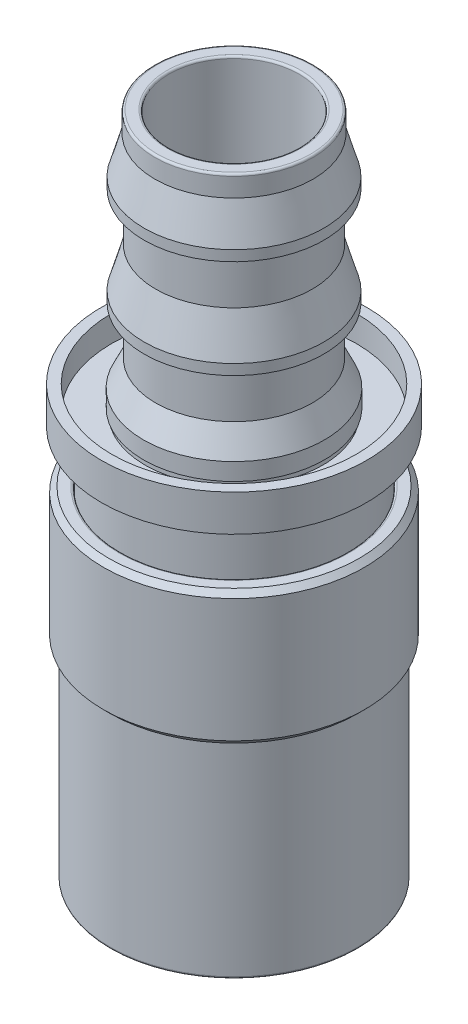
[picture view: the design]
ISO-10303-21;
HEADER;
FILE_DESCRIPTION(('STEP AP214'),'2;1');
FILE_NAME('part.step','',(''),(''),'','','');
FILE_SCHEMA(('AUTOMOTIVE_DESIGN { 1 0 10303 214 1 1 1 1 }'));
ENDSEC;
DATA;
#1=APPLICATION_CONTEXT('core data for automotive mechanical design processes');
#2=APPLICATION_PROTOCOL_DEFINITION('international standard','automotive_design',2000,#1);
#3=PRODUCT_CONTEXT('',#1,'mechanical');
#4=PRODUCT('Part','Part','',(#3));
#5=PRODUCT_RELATED_PRODUCT_CATEGORY('part','',(#4));
#6=PRODUCT_DEFINITION_FORMATION('','',#4);
#7=PRODUCT_DEFINITION_CONTEXT('part definition',#1,'design');
#8=PRODUCT_DEFINITION('design','',#6,#7);
#9=PRODUCT_DEFINITION_SHAPE('','',#8);
#10=(LENGTH_UNIT() NAMED_UNIT(*) SI_UNIT(.MILLI.,.METRE.));
#11=(NAMED_UNIT(*) PLANE_ANGLE_UNIT() SI_UNIT($,.RADIAN.));
#12=(NAMED_UNIT(*) SI_UNIT($,.STERADIAN.) SOLID_ANGLE_UNIT());
#13=UNCERTAINTY_MEASURE_WITH_UNIT(LENGTH_MEASURE(1.E-05),#10,'distance_accuracy_value','');
#14=(GEOMETRIC_REPRESENTATION_CONTEXT(3) GLOBAL_UNCERTAINTY_ASSIGNED_CONTEXT((#13)) GLOBAL_UNIT_ASSIGNED_CONTEXT((#10,
#11,#12)) REPRESENTATION_CONTEXT('',''));
#15=CARTESIAN_POINT('',(0.,0.,0.));
#16=DIRECTION('',(0.,0.,1.));
#17=DIRECTION('',(1.,0.,0.));
#18=AXIS2_PLACEMENT_3D('',#15,#16,#17);
#19=CARTESIAN_POINT('',(0.,80.6958,0.));
#20=DIRECTION('',(0.,1.,0.));
#21=DIRECTION('',(0.,0.,1.));
#22=AXIS2_PLACEMENT_3D('',#19,#20,#21);
#23=TOROIDAL_SURFACE('',#22,8.1788,0.254);
#24=CARTESIAN_POINT('',(0.,80.6958,0.));
#25=DIRECTION('',(0.,-1.,0.));
#26=DIRECTION('',(0.,0.,-1.));
#27=AXIS2_PLACEMENT_3D('',#24,#25,#26);
#28=CIRCLE('',#27,7.9248);
#29=CARTESIAN_POINT('',(0.,80.6958,7.9248));
#30=VERTEX_POINT('',#29);
#31=CARTESIAN_POINT('',(0.,80.6958,-7.9248));
#32=VERTEX_POINT('',#31);
#33=EDGE_CURVE('P0_E11',#30,#32,#28,.T.);
#34=ORIENTED_EDGE('',*,*,#33,.T.);
#35=CARTESIAN_POINT('',(0.,80.6958,-8.1788));
#36=DIRECTION('',(-1.,0.,0.));
#37=DIRECTION('',(0.,0.,-1.));
#38=AXIS2_PLACEMENT_3D('',#35,#36,#37);
#39=CIRCLE('',#38,0.254);
#40=CARTESIAN_POINT('',(0.,80.9498,-8.1788));
#41=VERTEX_POINT('',#40);
#42=EDGE_CURVE('P0_E27',#32,#41,#39,.T.);
#43=ORIENTED_EDGE('',*,*,#42,.T.);
#44=CARTESIAN_POINT('',(0.,80.9498,0.));
#45=DIRECTION('',(0.,1.,0.));
#46=DIRECTION('',(0.,0.,-1.));
#47=AXIS2_PLACEMENT_3D('',#44,#45,#46);
#48=CIRCLE('',#47,8.1788);
#49=CARTESIAN_POINT('',(0.,80.9498,8.1788));
#50=VERTEX_POINT('',#49);
#51=EDGE_CURVE('P0_E329',#41,#50,#48,.T.);
#52=ORIENTED_EDGE('',*,*,#51,.T.);
#53=CARTESIAN_POINT('',(0.,80.9498,0.));
#54=DIRECTION('',(0.,1.,0.));
#55=DIRECTION('',(0.,0.,-1.));
#56=AXIS2_PLACEMENT_3D('',#53,#54,#55);
#57=CIRCLE('',#56,8.1788);
#58=EDGE_CURVE('P0_E300',#50,#41,#57,.T.);
#59=ORIENTED_EDGE('',*,*,#58,.T.);
#60=ORIENTED_EDGE('',*,*,#42,.F.);
#61=CARTESIAN_POINT('',(0.,80.6958,0.));
#62=DIRECTION('',(0.,-1.,0.));
#63=DIRECTION('',(0.,0.,-1.));
#64=AXIS2_PLACEMENT_3D('',#61,#62,#63);
#65=CIRCLE('',#64,7.9248);
#66=EDGE_CURVE('P0_E41',#32,#30,#65,.T.);
#67=ORIENTED_EDGE('',*,*,#66,.T.);
#68=EDGE_LOOP('',(#34,#43,#52,#59,#60,#67));
#69=FACE_BOUND('',#68,.T.);
#70=ADVANCED_FACE('P0_F16',(#69),#23,.T.);
#71=CARTESIAN_POINT('',(0.,80.9498,7.9248));
#72=DIRECTION('',(0.,1.,0.));
#73=DIRECTION('',(1.,0.,0.));
#74=AXIS2_PLACEMENT_3D('',#71,#72,#73);
#75=PLANE('',#74);
#76=CARTESIAN_POINT('',(0.,80.9498,0.));
#77=DIRECTION('',(0.,-1.,0.));
#78=DIRECTION('',(0.,0.,-1.));
#79=AXIS2_PLACEMENT_3D('',#76,#77,#78);
#80=CIRCLE('',#79,9.37286457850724);
#81=CARTESIAN_POINT('',(0.,80.9498,9.37286457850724));
#82=VERTEX_POINT('',#81);
#83=CARTESIAN_POINT('',(0.,80.9498,-9.37286457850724));
#84=VERTEX_POINT('',#83);
#85=EDGE_CURVE('P0_E335',#82,#84,#80,.T.);
#86=ORIENTED_EDGE('',*,*,#85,.F.);
#87=CARTESIAN_POINT('',(0.,80.9498,0.));
#88=DIRECTION('',(0.,-1.,0.));
#89=DIRECTION('',(0.,0.,-1.));
#90=AXIS2_PLACEMENT_3D('',#87,#88,#89);
#91=CIRCLE('',#90,9.37286457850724);
#92=EDGE_CURVE('P0_E310',#84,#82,#91,.T.);
#93=ORIENTED_EDGE('',*,*,#92,.F.);
#94=EDGE_LOOP('',(#86,#93));
#95=FACE_BOUND('',#94,.T.);
#96=ORIENTED_EDGE('',*,*,#58,.F.);
#97=ORIENTED_EDGE('',*,*,#51,.F.);
#98=EDGE_LOOP('',(#96,#97));
#99=FACE_BOUND('',#98,.T.);
#100=ADVANCED_FACE('P0_F606',(#95,#99),#75,.T.);
#101=CARTESIAN_POINT('',(0.,52.4637,0.));
#102=DIRECTION('',(0.,1.,0.));
#103=DIRECTION('',(0.,0.,1.));
#104=AXIS2_PLACEMENT_3D('',#101,#102,#103);
#105=CYLINDRICAL_SURFACE('',#104,7.9248);
#106=ORIENTED_EDGE('',*,*,#33,.F.);
#107=ORIENTED_EDGE('',*,*,#66,.F.);
#108=DIRECTION('',(0.,-1.,0.));
#109=VECTOR('',#108,1.);
#110=CARTESIAN_POINT('',(0.,52.4637,-7.9248));
#111=LINE('',#110,#109);
#112=CARTESIAN_POINT('',(0.,23.9776,-7.9248));
#113=VERTEX_POINT('',#112);
#114=EDGE_CURVE('P0_E332',#32,#113,#111,.T.);
#115=ORIENTED_EDGE('',*,*,#114,.T.);
#116=CARTESIAN_POINT('',(0.,23.9776,0.));
#117=DIRECTION('',(0.,1.,0.));
#118=DIRECTION('',(1.,0.,0.));
#119=AXIS2_PLACEMENT_3D('',#116,#117,#118);
#120=CIRCLE('',#119,7.9248);
#121=CARTESIAN_POINT('',(0.,23.9776,7.9248));
#122=VERTEX_POINT('',#121);
#123=EDGE_CURVE('P0_E435',#122,#113,#120,.T.);
#124=ORIENTED_EDGE('',*,*,#123,.F.);
#125=CARTESIAN_POINT('',(0.,23.9776,0.));
#126=DIRECTION('',(0.,1.,0.));
#127=DIRECTION('',(1.,0.,0.));
#128=AXIS2_PLACEMENT_3D('',#125,#126,#127);
#129=CIRCLE('',#128,7.9248);
#130=EDGE_CURVE('P0_E506',#113,#122,#129,.T.);
#131=ORIENTED_EDGE('',*,*,#130,.F.);
#132=ORIENTED_EDGE('',*,*,#114,.F.);
#133=EDGE_LOOP('',(#106,#107,#115,#124,#131,#132));
#134=FACE_BOUND('',#133,.T.);
#135=ADVANCED_FACE('P0_F613',(#134),#105,.F.);
#136=CARTESIAN_POINT('',(0.,80.6958,0.));
#137=DIRECTION('',(0.,1.,0.));
#138=DIRECTION('',(0.,0.,1.));
#139=AXIS2_PLACEMENT_3D('',#136,#137,#138);
#140=TOROIDAL_SURFACE('',#139,9.37286457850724,0.254);
#141=ORIENTED_EDGE('',*,*,#85,.T.);
#142=CARTESIAN_POINT('',(0.,80.6958,-9.37286457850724));
#143=DIRECTION('',(-1.,0.,0.));
#144=DIRECTION('',(0.,0.,-1.));
#145=AXIS2_PLACEMENT_3D('',#142,#143,#144);
#146=CIRCLE('',#145,0.254);
#147=CARTESIAN_POINT('',(0.,80.6958,-9.62686457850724));
#148=VERTEX_POINT('',#147);
#149=EDGE_CURVE('P0_E415',#84,#148,#146,.T.);
#150=ORIENTED_EDGE('',*,*,#149,.T.);
#151=CARTESIAN_POINT('',(0.,80.6958,0.));
#152=DIRECTION('',(0.,1.,0.));
#153=DIRECTION('',(0.,0.,-1.));
#154=AXIS2_PLACEMENT_3D('',#151,#152,#153);
#155=CIRCLE('',#154,9.62686457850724);
#156=CARTESIAN_POINT('',(0.,80.6958,9.62686457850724));
#157=VERTEX_POINT('',#156);
#158=EDGE_CURVE('P0_E366',#148,#157,#155,.T.);
#159=ORIENTED_EDGE('',*,*,#158,.T.);
#160=CARTESIAN_POINT('',(0.,80.6958,0.));
#161=DIRECTION('',(0.,1.,0.));
#162=DIRECTION('',(0.,0.,-1.));
#163=AXIS2_PLACEMENT_3D('',#160,#161,#162);
#164=CIRCLE('',#163,9.62686457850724);
#165=EDGE_CURVE('P0_E363',#157,#148,#164,.T.);
#166=ORIENTED_EDGE('',*,*,#165,.T.);
#167=ORIENTED_EDGE('',*,*,#149,.F.);
#168=ORIENTED_EDGE('',*,*,#92,.T.);
#169=EDGE_LOOP('',(#141,#150,#159,#166,#167,#168));
#170=FACE_BOUND('',#169,.T.);
#171=ADVANCED_FACE('P0_F675',(#170),#140,.T.);
#172=CARTESIAN_POINT('',(0.,79.6798,0.));
#173=DIRECTION('',(0.,1.,0.));
#174=DIRECTION('',(0.,0.,1.));
#175=AXIS2_PLACEMENT_3D('',#172,#173,#174);
#176=CYLINDRICAL_SURFACE('',#175,9.62686457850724);
#177=ORIENTED_EDGE('',*,*,#165,.F.);
#178=ORIENTED_EDGE('',*,*,#158,.F.);
#179=DIRECTION('',(0.,-1.,0.));
#180=VECTOR('',#179,1.);
#181=CARTESIAN_POINT('',(0.,79.6798,-9.62686457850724));
#182=LINE('',#181,#180);
#183=CARTESIAN_POINT('',(0.,78.4098,-9.62686457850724));
#184=VERTEX_POINT('',#183);
#185=EDGE_CURVE('P0_E306',#148,#184,#182,.T.);
#186=ORIENTED_EDGE('',*,*,#185,.T.);
#187=CARTESIAN_POINT('',(0.,78.4098,0.));
#188=DIRECTION('',(0.,1.,0.));
#189=DIRECTION('',(1.,0.,0.));
#190=AXIS2_PLACEMENT_3D('',#187,#188,#189);
#191=CIRCLE('',#190,9.62686457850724);
#192=CARTESIAN_POINT('',(0.,78.4098,9.62686457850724));
#193=VERTEX_POINT('',#192);
#194=EDGE_CURVE('P0_E311',#184,#193,#191,.T.);
#195=ORIENTED_EDGE('',*,*,#194,.T.);
#196=CARTESIAN_POINT('',(0.,78.4098,0.));
#197=DIRECTION('',(0.,1.,0.));
#198=DIRECTION('',(1.,0.,0.));
#199=AXIS2_PLACEMENT_3D('',#196,#197,#198);
#200=CIRCLE('',#199,9.62686457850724);
#201=EDGE_CURVE('P0_E408',#193,#184,#200,.T.);
#202=ORIENTED_EDGE('',*,*,#201,.T.);
#203=ORIENTED_EDGE('',*,*,#185,.F.);
#204=EDGE_LOOP('',(#177,#178,#186,#195,#202,#203));
#205=FACE_BOUND('',#204,.T.);
#206=ADVANCED_FACE('P0_F686',(#205),#176,.T.);
#207=CARTESIAN_POINT('',(0.,0.254,0.));
#208=DIRECTION('',(0.,1.,0.));
#209=DIRECTION('',(0.,0.,1.));
#210=AXIS2_PLACEMENT_3D('',#207,#208,#209);
#211=TOROIDAL_SURFACE('',#210,11.8618,0.254);
#212=CARTESIAN_POINT('',(0.,0.254,0.));
#213=DIRECTION('',(0.,-1.,0.));
#214=DIRECTION('',(0.,0.,-1.));
#215=AXIS2_PLACEMENT_3D('',#212,#213,#214);
#216=CIRCLE('',#215,12.1158);
#217=CARTESIAN_POINT('',(0.,0.254,12.1158));
#218=VERTEX_POINT('',#217);
#219=CARTESIAN_POINT('',(0.,0.254,-12.1158));
#220=VERTEX_POINT('',#219);
#221=EDGE_CURVE('P0_E411',#218,#220,#216,.T.);
#222=ORIENTED_EDGE('',*,*,#221,.T.);
#223=CARTESIAN_POINT('',(0.,0.254,-11.8618));
#224=DIRECTION('',(-1.,0.,0.));
#225=DIRECTION('',(0.,0.,-1.));
#226=AXIS2_PLACEMENT_3D('',#223,#224,#225);
#227=CIRCLE('',#226,0.254);
#228=CARTESIAN_POINT('',(0.,0.,-11.8618));
#229=VERTEX_POINT('',#228);
#230=EDGE_CURVE('P0_E459',#220,#229,#227,.T.);
#231=ORIENTED_EDGE('',*,*,#230,.T.);
#232=CARTESIAN_POINT('',(0.,0.,0.));
#233=DIRECTION('',(0.,1.,0.));
#234=DIRECTION('',(0.,0.,-1.));
#235=AXIS2_PLACEMENT_3D('',#232,#233,#234);
#236=CIRCLE('',#235,11.8618);
#237=CARTESIAN_POINT('',(0.,0.,11.8618));
#238=VERTEX_POINT('',#237);
#239=EDGE_CURVE('P0_E443',#229,#238,#236,.T.);
#240=ORIENTED_EDGE('',*,*,#239,.T.);
#241=CARTESIAN_POINT('',(0.,0.,0.));
#242=DIRECTION('',(0.,1.,0.));
#243=DIRECTION('',(0.,0.,-1.));
#244=AXIS2_PLACEMENT_3D('',#241,#242,#243);
#245=CIRCLE('',#244,11.8618);
#246=EDGE_CURVE('P0_E440',#238,#229,#245,.T.);
#247=ORIENTED_EDGE('',*,*,#246,.T.);
#248=ORIENTED_EDGE('',*,*,#230,.F.);
#249=CARTESIAN_POINT('',(0.,0.254,0.));
#250=DIRECTION('',(0.,-1.,0.));
#251=DIRECTION('',(0.,0.,-1.));
#252=AXIS2_PLACEMENT_3D('',#249,#250,#251);
#253=CIRCLE('',#252,12.1158);
#254=EDGE_CURVE('P0_E399',#220,#218,#253,.T.);
#255=ORIENTED_EDGE('',*,*,#254,.T.);
#256=EDGE_LOOP('',(#222,#231,#240,#247,#248,#255));
#257=FACE_BOUND('',#256,.T.);
#258=ADVANCED_FACE('P0_F689',(#257),#211,.T.);
#259=CARTESIAN_POINT('',(0.,0.,12.1158));
#260=DIRECTION('',(0.,-1.,0.));
#261=DIRECTION('',(0.,0.,-1.));
#262=AXIS2_PLACEMENT_3D('',#259,#260,#261);
#263=PLANE('',#262);
#264=ORIENTED_EDGE('',*,*,#246,.F.);
#265=ORIENTED_EDGE('',*,*,#239,.F.);
#266=EDGE_LOOP('',(#264,#265));
#267=FACE_BOUND('',#266,.T.);
#268=CARTESIAN_POINT('',(0.,0.,0.));
#269=DIRECTION('',(0.,-1.,0.));
#270=DIRECTION('',(0.,0.,-1.));
#271=AXIS2_PLACEMENT_3D('',#268,#269,#270);
#272=CIRCLE('',#271,11.1760003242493);
#273=CARTESIAN_POINT('',(0.,0.,11.1760003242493));
#274=VERTEX_POINT('',#273);
#275=EDGE_CURVE('P0_E286',#274,#274,#272,.T.);
#276=ORIENTED_EDGE('',*,*,#275,.F.);
#277=EDGE_LOOP('',(#276));
#278=FACE_BOUND('',#277,.T.);
#279=ADVANCED_FACE('P0_F650',(#267,#278),#263,.T.);
#280=CARTESIAN_POINT('',(0.,8.1153,0.));
#281=DIRECTION('',(0.,1.,0.));
#282=DIRECTION('',(0.,0.,1.));
#283=AXIS2_PLACEMENT_3D('',#280,#281,#282);
#284=CYLINDRICAL_SURFACE('',#283,12.1158);
#285=CARTESIAN_POINT('',(0.,16.2306,0.));
#286=DIRECTION('',(0.,1.,0.));
#287=DIRECTION('',(1.,0.,0.));
#288=AXIS2_PLACEMENT_3D('',#285,#286,#287);
#289=CIRCLE('',#288,12.1158);
#290=CARTESIAN_POINT('',(0.,16.2306,12.1158));
#291=VERTEX_POINT('',#290);
#292=CARTESIAN_POINT('',(0.,16.2306,-12.1158));
#293=VERTEX_POINT('',#292);
#294=EDGE_CURVE('P0_E336',#291,#293,#289,.T.);
#295=ORIENTED_EDGE('',*,*,#294,.F.);
#296=CARTESIAN_POINT('',(0.,16.2306,0.));
#297=DIRECTION('',(0.,1.,0.));
#298=DIRECTION('',(1.,0.,0.));
#299=AXIS2_PLACEMENT_3D('',#296,#297,#298);
#300=CIRCLE('',#299,12.1158);
#301=EDGE_CURVE('P0_E280',#293,#291,#300,.T.);
#302=ORIENTED_EDGE('',*,*,#301,.F.);
#303=DIRECTION('',(0.,-1.,0.));
#304=VECTOR('',#303,1.);
#305=CARTESIAN_POINT('',(0.,8.1153,-12.1158));
#306=LINE('',#305,#304);
#307=EDGE_CURVE('P0_E395',#293,#220,#306,.T.);
#308=ORIENTED_EDGE('',*,*,#307,.T.);
#309=ORIENTED_EDGE('',*,*,#221,.F.);
#310=ORIENTED_EDGE('',*,*,#254,.F.);
#311=ORIENTED_EDGE('',*,*,#307,.F.);
#312=EDGE_LOOP('',(#295,#302,#308,#309,#310,#311));
#313=FACE_BOUND('',#312,.T.);
#314=ADVANCED_FACE('P0_F601',(#313),#284,.T.);
#315=CARTESIAN_POINT('',(0.,16.4846,0.));
#316=DIRECTION('',(0.,1.,0.));
#317=DIRECTION('',(0.,0.,1.));
#318=AXIS2_PLACEMENT_3D('',#315,#316,#317);
#319=TOROIDAL_SURFACE('',#318,13.4874,0.254);
#320=CARTESIAN_POINT('',(0.,16.4846,0.));
#321=DIRECTION('',(0.,-1.,0.));
#322=DIRECTION('',(0.,0.,-1.));
#323=AXIS2_PLACEMENT_3D('',#320,#321,#322);
#324=CIRCLE('',#323,13.7414);
#325=CARTESIAN_POINT('',(0.,16.4846,13.7414));
#326=VERTEX_POINT('',#325);
#327=CARTESIAN_POINT('',(0.,16.4846,-13.7414));
#328=VERTEX_POINT('',#327);
#329=EDGE_CURVE('P0_E400',#326,#328,#324,.T.);
#330=ORIENTED_EDGE('',*,*,#329,.T.);
#331=CARTESIAN_POINT('',(0.,16.4846,-13.4874));
#332=DIRECTION('',(-1.,0.,0.));
#333=DIRECTION('',(0.,0.,-1.));
#334=AXIS2_PLACEMENT_3D('',#331,#332,#333);
#335=CIRCLE('',#334,0.254);
#336=CARTESIAN_POINT('',(0.,16.2306,-13.4874));
#337=VERTEX_POINT('',#336);
#338=EDGE_CURVE('P0_E448',#328,#337,#335,.T.);
#339=ORIENTED_EDGE('',*,*,#338,.T.);
#340=CARTESIAN_POINT('',(0.,16.2306,0.));
#341=DIRECTION('',(0.,1.,0.));
#342=DIRECTION('',(0.,0.,-1.));
#343=AXIS2_PLACEMENT_3D('',#340,#341,#342);
#344=CIRCLE('',#343,13.4874);
#345=CARTESIAN_POINT('',(0.,16.2306,13.4874));
#346=VERTEX_POINT('',#345);
#347=EDGE_CURVE('P0_E488',#337,#346,#344,.T.);
#348=ORIENTED_EDGE('',*,*,#347,.T.);
#349=CARTESIAN_POINT('',(0.,16.2306,0.));
#350=DIRECTION('',(0.,1.,0.));
#351=DIRECTION('',(0.,0.,-1.));
#352=AXIS2_PLACEMENT_3D('',#349,#350,#351);
#353=CIRCLE('',#352,13.4874);
#354=EDGE_CURVE('P0_E451',#346,#337,#353,.T.);
#355=ORIENTED_EDGE('',*,*,#354,.T.);
#356=ORIENTED_EDGE('',*,*,#338,.F.);
#357=CARTESIAN_POINT('',(0.,16.4846,0.));
#358=DIRECTION('',(0.,-1.,0.));
#359=DIRECTION('',(0.,0.,-1.));
#360=AXIS2_PLACEMENT_3D('',#357,#358,#359);
#361=CIRCLE('',#360,13.7414);
#362=EDGE_CURVE('P0_E382',#328,#326,#361,.T.);
#363=ORIENTED_EDGE('',*,*,#362,.T.);
#364=EDGE_LOOP('',(#330,#339,#348,#355,#356,#363));
#365=FACE_BOUND('',#364,.T.);
#366=ADVANCED_FACE('P0_F584',(#365),#319,.T.);
#367=CARTESIAN_POINT('',(0.,31.9149084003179,0.));
#368=DIRECTION('',(0.,1.,0.));
#369=DIRECTION('',(0.,0.,1.));
#370=AXIS2_PLACEMENT_3D('',#367,#368,#369);
#371=CYLINDRICAL_SURFACE('',#370,13.7414);
#372=CARTESIAN_POINT('',(0.,47.3452168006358,0.));
#373=DIRECTION('',(0.,1.,0.));
#374=DIRECTION('',(0.,0.,-1.));
#375=AXIS2_PLACEMENT_3D('',#372,#373,#374);
#376=CIRCLE('',#375,13.7414);
#377=CARTESIAN_POINT('',(0.,47.3452168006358,13.7414));
#378=VERTEX_POINT('',#377);
#379=CARTESIAN_POINT('',(0.,47.3452168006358,-13.7414));
#380=VERTEX_POINT('',#379);
#381=EDGE_CURVE('P0_E285',#378,#380,#376,.T.);
#382=ORIENTED_EDGE('',*,*,#381,.F.);
#383=CARTESIAN_POINT('',(0.,47.3452168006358,0.));
#384=DIRECTION('',(0.,1.,0.));
#385=DIRECTION('',(0.,0.,-1.));
#386=AXIS2_PLACEMENT_3D('',#383,#384,#385);
#387=CIRCLE('',#386,13.7414);
#388=EDGE_CURVE('P0_E293',#380,#378,#387,.T.);
#389=ORIENTED_EDGE('',*,*,#388,.F.);
#390=DIRECTION('',(0.,-1.,0.));
#391=VECTOR('',#390,1.);
#392=CARTESIAN_POINT('',(0.,31.9149084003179,-13.7414));
#393=LINE('',#392,#391);
#394=EDGE_CURVE('P0_E340',#380,#328,#393,.T.);
#395=ORIENTED_EDGE('',*,*,#394,.T.);
#396=ORIENTED_EDGE('',*,*,#329,.F.);
#397=ORIENTED_EDGE('',*,*,#362,.F.);
#398=ORIENTED_EDGE('',*,*,#394,.F.);
#399=EDGE_LOOP('',(#382,#389,#395,#396,#397,#398));
#400=FACE_BOUND('',#399,.T.);
#401=ADVANCED_FACE('P0_F591',(#400),#371,.T.);
#402=CARTESIAN_POINT('',(0.,16.2306,13.7414));
#403=DIRECTION('',(0.,-1.,0.));
#404=DIRECTION('',(0.,0.,-1.));
#405=AXIS2_PLACEMENT_3D('',#402,#403,#404);
#406=PLANE('',#405);
#407=ORIENTED_EDGE('',*,*,#354,.F.);
#408=ORIENTED_EDGE('',*,*,#347,.F.);
#409=EDGE_LOOP('',(#407,#408));
#410=FACE_BOUND('',#409,.T.);
#411=ORIENTED_EDGE('',*,*,#294,.T.);
#412=ORIENTED_EDGE('',*,*,#301,.T.);
#413=EDGE_LOOP('',(#411,#412));
#414=FACE_BOUND('',#413,.T.);
#415=ADVANCED_FACE('P0_F586',(#410,#414),#406,.T.);
#416=CARTESIAN_POINT('',(0.,47.3452168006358,0.));
#417=DIRECTION('',(0.,1.,0.));
#418=DIRECTION('',(0.,0.,1.));
#419=AXIS2_PLACEMENT_3D('',#416,#417,#418);
#420=TOROIDAL_SURFACE('',#419,13.4874,0.254);
#421=CARTESIAN_POINT('',(0.,47.5992168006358,0.));
#422=DIRECTION('',(0.,-1.,0.));
#423=DIRECTION('',(0.,0.,-1.));
#424=AXIS2_PLACEMENT_3D('',#421,#422,#423);
#425=CIRCLE('',#424,13.4874);
#426=CARTESIAN_POINT('',(0.,47.5992168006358,13.4874));
#427=VERTEX_POINT('',#426);
#428=CARTESIAN_POINT('',(0.,47.5992168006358,-13.4874));
#429=VERTEX_POINT('',#428);
#430=EDGE_CURVE('P0_E272',#427,#429,#425,.T.);
#431=ORIENTED_EDGE('',*,*,#430,.T.);
#432=CARTESIAN_POINT('',(0.,47.3452168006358,-13.4874));
#433=DIRECTION('',(-1.,0.,0.));
#434=DIRECTION('',(0.,0.,-1.));
#435=AXIS2_PLACEMENT_3D('',#432,#433,#434);
#436=CIRCLE('',#435,0.254);
#437=EDGE_CURVE('P0_E281',#429,#380,#436,.T.);
#438=ORIENTED_EDGE('',*,*,#437,.T.);
#439=ORIENTED_EDGE('',*,*,#388,.T.);
#440=ORIENTED_EDGE('',*,*,#381,.T.);
#441=ORIENTED_EDGE('',*,*,#437,.F.);
#442=CARTESIAN_POINT('',(0.,47.5992168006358,0.));
#443=DIRECTION('',(0.,-1.,0.));
#444=DIRECTION('',(0.,0.,-1.));
#445=AXIS2_PLACEMENT_3D('',#442,#443,#444);
#446=CIRCLE('',#445,13.4874);
#447=EDGE_CURVE('P0_E276',#429,#427,#446,.T.);
#448=ORIENTED_EDGE('',*,*,#447,.T.);
#449=EDGE_LOOP('',(#431,#438,#439,#440,#441,#448));
#450=FACE_BOUND('',#449,.T.);
#451=ADVANCED_FACE('P0_F283',(#450),#420,.T.);
#452=CARTESIAN_POINT('',(0.,47.5992168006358,10.4648));
#453=DIRECTION('',(0.,1.,0.));
#454=DIRECTION('',(1.,0.,0.));
#455=AXIS2_PLACEMENT_3D('',#452,#453,#454);
#456=PLANE('',#455);
#457=ORIENTED_EDGE('',*,*,#430,.F.);
#458=ORIENTED_EDGE('',*,*,#447,.F.);
#459=EDGE_LOOP('',(#457,#458));
#460=FACE_BOUND('',#459,.T.);
#461=CARTESIAN_POINT('',(0.,47.5992168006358,0.));
#462=DIRECTION('',(0.,1.,0.));
#463=DIRECTION('',(1.,0.,0.));
#464=AXIS2_PLACEMENT_3D('',#461,#462,#463);
#465=CIRCLE('',#464,10.4648);
#466=CARTESIAN_POINT('',(0.,47.5992168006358,10.4648));
#467=VERTEX_POINT('',#466);
#468=CARTESIAN_POINT('',(0.,47.5992168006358,-10.4648));
#469=VERTEX_POINT('',#468);
#470=EDGE_CURVE('P0_E318',#467,#469,#465,.T.);
#471=ORIENTED_EDGE('',*,*,#470,.F.);
#472=CARTESIAN_POINT('',(0.,47.5992168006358,0.));
#473=DIRECTION('',(0.,1.,0.));
#474=DIRECTION('',(1.,0.,0.));
#475=AXIS2_PLACEMENT_3D('',#472,#473,#474);
#476=CIRCLE('',#475,10.4648);
#477=EDGE_CURVE('P0_E321',#469,#467,#476,.T.);
#478=ORIENTED_EDGE('',*,*,#477,.F.);
#479=EDGE_LOOP('',(#471,#478));
#480=FACE_BOUND('',#479,.T.);
#481=ADVANCED_FACE('P0_F274',(#460,#480),#456,.T.);
#482=CARTESIAN_POINT('',(0.,0.508,0.));
#483=DIRECTION('',(0.,-1.,0.));
#484=DIRECTION('',(0.,0.,-1.));
#485=AXIS2_PLACEMENT_3D('',#482,#483,#484);
#486=CONICAL_SURFACE('',#485,10.6680003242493,0.785398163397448);
#487=ORIENTED_EDGE('',*,*,#275,.T.);
#488=DIRECTION('',(0.,0.707106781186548,-0.707106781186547));
#489=VECTOR('',#488,1.);
#490=CARTESIAN_POINT('',(0.,0.508,10.6680003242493));
#491=LINE('',#490,#489);
#492=CARTESIAN_POINT('',(0.,1.016,10.1600003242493));
#493=VERTEX_POINT('',#492);
#494=EDGE_CURVE('P0_E296',#274,#493,#491,.T.);
#495=ORIENTED_EDGE('',*,*,#494,.T.);
#496=CARTESIAN_POINT('',(0.,1.016,0.));
#497=DIRECTION('',(0.,1.,0.));
#498=DIRECTION('',(0.,0.,-1.));
#499=AXIS2_PLACEMENT_3D('',#496,#497,#498);
#500=CIRCLE('',#499,10.1600003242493);
#501=CARTESIAN_POINT('',(0.,1.016,-10.1600003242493));
#502=VERTEX_POINT('',#501);
#503=EDGE_CURVE('P0_E418',#493,#502,#500,.T.);
#504=ORIENTED_EDGE('',*,*,#503,.T.);
#505=CARTESIAN_POINT('',(0.,1.016,0.));
#506=DIRECTION('',(0.,1.,0.));
#507=DIRECTION('',(0.,0.,-1.));
#508=AXIS2_PLACEMENT_3D('',#505,#506,#507);
#509=CIRCLE('',#508,10.1600003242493);
#510=EDGE_CURVE('P0_E422',#502,#493,#509,.T.);
#511=ORIENTED_EDGE('',*,*,#510,.T.);
#512=ORIENTED_EDGE('',*,*,#494,.F.);
#513=EDGE_LOOP('',(#487,#495,#504,#511,#512));
#514=FACE_BOUND('',#513,.T.);
#515=ADVANCED_FACE('P0_F629',(#514),#486,.F.);
#516=CARTESIAN_POINT('',(0.,8.59790016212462,0.));
#517=DIRECTION('',(0.,1.,0.));
#518=DIRECTION('',(0.,0.,1.));
#519=AXIS2_PLACEMENT_3D('',#516,#517,#518);
#520=CYLINDRICAL_SURFACE('',#519,10.1600003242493);
#521=CARTESIAN_POINT('',(0.,17.1958003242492,0.));
#522=DIRECTION('',(0.,1.,0.));
#523=DIRECTION('',(1.,0.,0.));
#524=AXIS2_PLACEMENT_3D('',#521,#522,#523);
#525=CIRCLE('',#524,10.1600003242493);
#526=CARTESIAN_POINT('',(0.,17.1958003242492,10.1600003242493));
#527=VERTEX_POINT('',#526);
#528=CARTESIAN_POINT('',(0.,17.1958003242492,-10.1600003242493));
#529=VERTEX_POINT('',#528);
#530=EDGE_CURVE('P0_E355',#527,#529,#525,.T.);
#531=ORIENTED_EDGE('',*,*,#530,.T.);
#532=DIRECTION('',(0.,-1.,0.));
#533=VECTOR('',#532,1.);
#534=CARTESIAN_POINT('',(0.,8.59790016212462,-10.1600003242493));
#535=LINE('',#534,#533);
#536=EDGE_CURVE('P0_E351',#529,#502,#535,.T.);
#537=ORIENTED_EDGE('',*,*,#536,.T.);
#538=ORIENTED_EDGE('',*,*,#503,.F.);
#539=ORIENTED_EDGE('',*,*,#510,.F.);
#540=ORIENTED_EDGE('',*,*,#536,.F.);
#541=CARTESIAN_POINT('',(0.,17.1958003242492,0.));
#542=DIRECTION('',(0.,1.,0.));
#543=DIRECTION('',(1.,0.,0.));
#544=AXIS2_PLACEMENT_3D('',#541,#542,#543);
#545=CIRCLE('',#544,10.1600003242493);
#546=EDGE_CURVE('P0_E356',#529,#527,#545,.T.);
#547=ORIENTED_EDGE('',*,*,#546,.T.);
#548=EDGE_LOOP('',(#531,#537,#538,#539,#540,#547));
#549=FACE_BOUND('',#548,.T.);
#550=ADVANCED_FACE('P0_F638',(#549),#520,.F.);
#551=CARTESIAN_POINT('',(0.,23.9776,10.668));
#552=DIRECTION('',(0.,-1.,0.));
#553=DIRECTION('',(0.,0.,-1.));
#554=AXIS2_PLACEMENT_3D('',#551,#552,#553);
#555=PLANE('',#554);
#556=CARTESIAN_POINT('',(0.,23.9776,0.));
#557=DIRECTION('',(0.,1.,0.));
#558=DIRECTION('',(1.,0.,0.));
#559=AXIS2_PLACEMENT_3D('',#556,#557,#558);
#560=CIRCLE('',#559,10.668);
#561=CARTESIAN_POINT('',(0.,23.9776,10.668));
#562=VERTEX_POINT('',#561);
#563=CARTESIAN_POINT('',(0.,23.9776,-10.668));
#564=VERTEX_POINT('',#563);
#565=EDGE_CURVE('P0_E501',#562,#564,#560,.T.);
#566=ORIENTED_EDGE('',*,*,#565,.F.);
#567=CARTESIAN_POINT('',(0.,23.9776,0.));
#568=DIRECTION('',(0.,1.,0.));
#569=DIRECTION('',(1.,0.,0.));
#570=AXIS2_PLACEMENT_3D('',#567,#568,#569);
#571=CIRCLE('',#570,10.668);
#572=EDGE_CURVE('P0_E20',#564,#562,#571,.T.);
#573=ORIENTED_EDGE('',*,*,#572,.F.);
#574=EDGE_LOOP('',(#566,#573));
#575=FACE_BOUND('',#574,.T.);
#576=ORIENTED_EDGE('',*,*,#123,.T.);
#577=ORIENTED_EDGE('',*,*,#130,.T.);
#578=EDGE_LOOP('',(#576,#577));
#579=FACE_BOUND('',#578,.T.);
#580=ADVANCED_FACE('P0_F635',(#575,#579),#555,.T.);
#581=CARTESIAN_POINT('',(0.,20.8407,0.));
#582=DIRECTION('',(0.,1.,0.));
#583=DIRECTION('',(0.,0.,1.));
#584=AXIS2_PLACEMENT_3D('',#581,#582,#583);
#585=CYLINDRICAL_SURFACE('',#584,10.668);
#586=ORIENTED_EDGE('',*,*,#565,.T.);
#587=DIRECTION('',(0.,-1.,0.));
#588=VECTOR('',#587,1.);
#589=CARTESIAN_POINT('',(0.,20.8407,-10.668));
#590=LINE('',#589,#588);
#591=CARTESIAN_POINT('',(0.,17.7038,-10.668));
#592=VERTEX_POINT('',#591);
#593=EDGE_CURVE('P0_E497',#564,#592,#590,.T.);
#594=ORIENTED_EDGE('',*,*,#593,.T.);
#595=CARTESIAN_POINT('',(0.,17.7038,0.));
#596=DIRECTION('',(0.,1.,0.));
#597=DIRECTION('',(1.,0.,0.));
#598=AXIS2_PLACEMENT_3D('',#595,#596,#597);
#599=CIRCLE('',#598,10.668);
#600=CARTESIAN_POINT('',(0.,17.7038,10.668));
#601=VERTEX_POINT('',#600);
#602=EDGE_CURVE('P0_E361',#601,#592,#599,.T.);
#603=ORIENTED_EDGE('',*,*,#602,.F.);
#604=CARTESIAN_POINT('',(0.,17.7038,0.));
#605=DIRECTION('',(0.,1.,0.));
#606=DIRECTION('',(1.,0.,0.));
#607=AXIS2_PLACEMENT_3D('',#604,#605,#606);
#608=CIRCLE('',#607,10.668);
#609=EDGE_CURVE('P0_E362',#592,#601,#608,.T.);
#610=ORIENTED_EDGE('',*,*,#609,.F.);
#611=ORIENTED_EDGE('',*,*,#593,.F.);
#612=ORIENTED_EDGE('',*,*,#572,.T.);
#613=EDGE_LOOP('',(#586,#594,#603,#610,#611,#612));
#614=FACE_BOUND('',#613,.T.);
#615=ADVANCED_FACE('P0_F623',(#614),#585,.F.);
#616=CARTESIAN_POINT('',(0.,17.4498001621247,0.));
#617=DIRECTION('',(0.,1.,0.));
#618=DIRECTION('',(0.,0.,1.));
#619=AXIS2_PLACEMENT_3D('',#616,#617,#618);
#620=CONICAL_SURFACE('',#619,10.4140001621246,0.785398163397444);
#621=ORIENTED_EDGE('',*,*,#602,.T.);
#622=DIRECTION('',(0.,-0.707106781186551,0.707106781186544));
#623=VECTOR('',#622,1.);
#624=CARTESIAN_POINT('',(0.,17.4498001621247,-10.4140001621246));
#625=LINE('',#624,#623);
#626=EDGE_CURVE('P0_E357',#592,#529,#625,.T.);
#627=ORIENTED_EDGE('',*,*,#626,.T.);
#628=ORIENTED_EDGE('',*,*,#530,.F.);
#629=ORIENTED_EDGE('',*,*,#546,.F.);
#630=ORIENTED_EDGE('',*,*,#626,.F.);
#631=ORIENTED_EDGE('',*,*,#609,.T.);
#632=EDGE_LOOP('',(#621,#627,#628,#629,#630,#631));
#633=FACE_BOUND('',#632,.T.);
#634=ADVANCED_FACE('P0_F619',(#633),#620,.F.);
#635=CARTESIAN_POINT('',(0.,48.5646084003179,0.));
#636=DIRECTION('',(0.,1.,0.));
#637=DIRECTION('',(0.,0.,1.));
#638=AXIS2_PLACEMENT_3D('',#635,#636,#637);
#639=CYLINDRICAL_SURFACE('',#638,10.4648);
#640=CARTESIAN_POINT('',(0.,49.53,0.));
#641=DIRECTION('',(0.,1.,0.));
#642=DIRECTION('',(1.,0.,0.));
#643=AXIS2_PLACEMENT_3D('',#640,#641,#642);
#644=CIRCLE('',#643,10.4648);
#645=CARTESIAN_POINT('',(0.,49.53,10.4648));
#646=VERTEX_POINT('',#645);
#647=CARTESIAN_POINT('',(0.,49.53,-10.4648));
#648=VERTEX_POINT('',#647);
#649=EDGE_CURVE('P0_E322',#646,#648,#644,.T.);
#650=ORIENTED_EDGE('',*,*,#649,.F.);
#651=CARTESIAN_POINT('',(0.,49.53,0.));
#652=DIRECTION('',(0.,1.,0.));
#653=DIRECTION('',(1.,0.,0.));
#654=AXIS2_PLACEMENT_3D('',#651,#652,#653);
#655=CIRCLE('',#654,10.4648);
#656=EDGE_CURVE('P0_E378',#648,#646,#655,.T.);
#657=ORIENTED_EDGE('',*,*,#656,.F.);
#658=DIRECTION('',(0.,-1.,0.));
#659=VECTOR('',#658,1.);
#660=CARTESIAN_POINT('',(0.,48.5646084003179,-10.4648));
#661=LINE('',#660,#659);
#662=EDGE_CURVE('P0_E350',#648,#469,#661,.T.);
#663=ORIENTED_EDGE('',*,*,#662,.T.);
#664=ORIENTED_EDGE('',*,*,#477,.T.);
#665=ORIENTED_EDGE('',*,*,#470,.T.);
#666=ORIENTED_EDGE('',*,*,#662,.F.);
#667=EDGE_LOOP('',(#650,#657,#663,#664,#665,#666));
#668=FACE_BOUND('',#667,.T.);
#669=ADVANCED_FACE('P0_F622',(#668),#639,.T.);
#670=CARTESIAN_POINT('',(0.,49.53,10.9982));
#671=DIRECTION('',(0.,-1.,0.));
#672=DIRECTION('',(0.,0.,-1.));
#673=AXIS2_PLACEMENT_3D('',#670,#671,#672);
#674=PLANE('',#673);
#675=CARTESIAN_POINT('',(0.,49.53,0.));
#676=DIRECTION('',(0.,1.,0.));
#677=DIRECTION('',(1.,0.,0.));
#678=AXIS2_PLACEMENT_3D('',#675,#676,#677);
#679=CIRCLE('',#678,10.9982);
#680=CARTESIAN_POINT('',(0.,49.53,10.9982));
#681=VERTEX_POINT('',#680);
#682=CARTESIAN_POINT('',(0.,49.53,-10.9982));
#683=VERTEX_POINT('',#682);
#684=EDGE_CURVE('P0_E394',#681,#683,#679,.T.);
#685=ORIENTED_EDGE('',*,*,#684,.F.);
#686=CARTESIAN_POINT('',(0.,49.53,0.));
#687=DIRECTION('',(0.,1.,0.));
#688=DIRECTION('',(1.,0.,0.));
#689=AXIS2_PLACEMENT_3D('',#686,#687,#688);
#690=CIRCLE('',#689,10.9982);
#691=EDGE_CURVE('P0_E389',#683,#681,#690,.T.);
#692=ORIENTED_EDGE('',*,*,#691,.F.);
#693=EDGE_LOOP('',(#685,#692));
#694=FACE_BOUND('',#693,.T.);
#695=ORIENTED_EDGE('',*,*,#649,.T.);
#696=ORIENTED_EDGE('',*,*,#656,.T.);
#697=EDGE_LOOP('',(#695,#696));
#698=FACE_BOUND('',#697,.T.);
#699=ADVANCED_FACE('P0_F661',(#694,#698),#674,.T.);
#700=CARTESIAN_POINT('',(0.,50.5792613,0.));
#701=DIRECTION('',(0.,-1.,0.));
#702=DIRECTION('',(0.,0.,1.));
#703=AXIS2_PLACEMENT_3D('',#700,#701,#702);
#704=CONICAL_SURFACE('',#703,10.9981976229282,2.26546661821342E-06);
#705=CARTESIAN_POINT('',(0.,51.6285226,0.));
#706=DIRECTION('',(0.,1.,0.));
#707=DIRECTION('',(1.,0.,0.));
#708=AXIS2_PLACEMENT_3D('',#705,#706,#707);
#709=CIRCLE('',#708,10.9981952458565);
#710=CARTESIAN_POINT('',(0.,51.6285226,10.9981952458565));
#711=VERTEX_POINT('',#710);
#712=CARTESIAN_POINT('',(0.,51.6285226,-10.9981952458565));
#713=VERTEX_POINT('',#712);
#714=EDGE_CURVE('P0_E407',#711,#713,#709,.T.);
#715=ORIENTED_EDGE('',*,*,#714,.F.);
#716=CARTESIAN_POINT('',(0.,51.6285226,0.));
#717=DIRECTION('',(0.,1.,0.));
#718=DIRECTION('',(1.,0.,0.));
#719=AXIS2_PLACEMENT_3D('',#716,#717,#718);
#720=CIRCLE('',#719,10.9981952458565);
#721=EDGE_CURVE('P0_E472',#713,#711,#720,.T.);
#722=ORIENTED_EDGE('',*,*,#721,.F.);
#723=DIRECTION('',(0.,-0.999999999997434,-2.26547168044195E-06));
#724=VECTOR('',#723,1.);
#725=CARTESIAN_POINT('',(0.,50.5792613,-10.9981976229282));
#726=LINE('',#725,#724);
#727=EDGE_CURVE('P0_E393',#713,#683,#726,.T.);
#728=ORIENTED_EDGE('',*,*,#727,.T.);
#729=ORIENTED_EDGE('',*,*,#691,.T.);
#730=ORIENTED_EDGE('',*,*,#684,.T.);
#731=ORIENTED_EDGE('',*,*,#727,.F.);
#732=EDGE_LOOP('',(#715,#722,#728,#729,#730,#731));
#733=FACE_BOUND('',#732,.T.);
#734=ADVANCED_FACE('P0_F634',(#733),#704,.T.);
#735=CARTESIAN_POINT('',(0.,53.2081613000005,0.));
#736=DIRECTION('',(0.,-1.,0.));
#737=DIRECTION('',(0.,0.,1.));
#738=AXIS2_PLACEMENT_3D('',#735,#736,#737);
#739=CONICAL_SURFACE('',#738,10.2615976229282,0.436332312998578);
#740=CARTESIAN_POINT('',(0.,54.787800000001,0.));
#741=DIRECTION('',(0.,1.,0.));
#742=DIRECTION('',(1.,0.,0.));
#743=AXIS2_PLACEMENT_3D('',#740,#741,#742);
#744=CIRCLE('',#743,9.525);
#745=CARTESIAN_POINT('',(0.,54.787800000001,9.525));
#746=VERTEX_POINT('',#745);
#747=CARTESIAN_POINT('',(0.,54.787800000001,-9.525));
#748=VERTEX_POINT('',#747);
#749=EDGE_CURVE('P0_E328',#746,#748,#744,.T.);
#750=ORIENTED_EDGE('',*,*,#749,.F.);
#751=CARTESIAN_POINT('',(0.,54.787800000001,0.));
#752=DIRECTION('',(0.,1.,0.));
#753=DIRECTION('',(1.,0.,0.));
#754=AXIS2_PLACEMENT_3D('',#751,#752,#753);
#755=CIRCLE('',#754,9.525);
#756=EDGE_CURVE('P0_E323',#748,#746,#755,.T.);
#757=ORIENTED_EDGE('',*,*,#756,.F.);
#758=DIRECTION('',(0.,-0.906307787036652,-0.422618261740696));
#759=VECTOR('',#758,1.);
#760=CARTESIAN_POINT('',(0.,53.2081613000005,-10.2615976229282));
#761=LINE('',#760,#759);
#762=EDGE_CURVE('P0_E535',#748,#713,#761,.T.);
#763=ORIENTED_EDGE('',*,*,#762,.T.);
#764=ORIENTED_EDGE('',*,*,#721,.T.);
#765=ORIENTED_EDGE('',*,*,#714,.T.);
#766=ORIENTED_EDGE('',*,*,#762,.F.);
#767=EDGE_LOOP('',(#750,#757,#763,#764,#765,#766));
#768=FACE_BOUND('',#767,.T.);
#769=ADVANCED_FACE('P0_F630',(#768),#739,.T.);
#770=CARTESIAN_POINT('',(0.,57.708800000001,0.));
#771=DIRECTION('',(0.,1.,0.));
#772=DIRECTION('',(0.,0.,1.));
#773=AXIS2_PLACEMENT_3D('',#770,#771,#772);
#774=CYLINDRICAL_SURFACE('',#773,9.525);
#775=CARTESIAN_POINT('',(0.,60.629800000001,0.));
#776=DIRECTION('',(0.,1.,0.));
#777=DIRECTION('',(1.,0.,0.));
#778=AXIS2_PLACEMENT_3D('',#775,#776,#777);
#779=CIRCLE('',#778,9.525);
#780=CARTESIAN_POINT('',(0.,60.629800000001,9.525));
#781=VERTEX_POINT('',#780);
#782=CARTESIAN_POINT('',(0.,60.629800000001,-9.525));
#783=VERTEX_POINT('',#782);
#784=EDGE_CURVE('P0_E431',#781,#783,#779,.T.);
#785=ORIENTED_EDGE('',*,*,#784,.F.);
#786=CARTESIAN_POINT('',(0.,60.629800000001,0.));
#787=DIRECTION('',(0.,1.,0.));
#788=DIRECTION('',(1.,0.,0.));
#789=AXIS2_PLACEMENT_3D('',#786,#787,#788);
#790=CIRCLE('',#789,9.525);
#791=EDGE_CURVE('P0_E479',#783,#781,#790,.T.);
#792=ORIENTED_EDGE('',*,*,#791,.F.);
#793=DIRECTION('',(0.,-1.,0.));
#794=VECTOR('',#793,1.);
#795=CARTESIAN_POINT('',(0.,57.708800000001,-9.525));
#796=LINE('',#795,#794);
#797=EDGE_CURVE('P0_E327',#783,#748,#796,.T.);
#798=ORIENTED_EDGE('',*,*,#797,.T.);
#799=ORIENTED_EDGE('',*,*,#756,.T.);
#800=ORIENTED_EDGE('',*,*,#749,.T.);
#801=ORIENTED_EDGE('',*,*,#797,.F.);
#802=EDGE_LOOP('',(#785,#792,#798,#799,#800,#801));
#803=FACE_BOUND('',#802,.T.);
#804=ADVANCED_FACE('P0_F633',(#803),#774,.T.);
#805=CARTESIAN_POINT('',(0.,60.6298,10.922));
#806=DIRECTION('',(0.,-1.,0.));
#807=DIRECTION('',(0.,0.,-1.));
#808=AXIS2_PLACEMENT_3D('',#805,#806,#807);
#809=PLANE('',#808);
#810=CARTESIAN_POINT('',(0.,60.6298,0.));
#811=DIRECTION('',(0.,1.,0.));
#812=DIRECTION('',(1.,0.,0.));
#813=AXIS2_PLACEMENT_3D('',#810,#811,#812);
#814=CIRCLE('',#813,10.922);
#815=CARTESIAN_POINT('',(0.,60.6298,10.922));
#816=VERTEX_POINT('',#815);
#817=CARTESIAN_POINT('',(0.,60.6298,-10.922));
#818=VERTEX_POINT('',#817);
#819=EDGE_CURVE('P0_E75',#816,#818,#814,.T.);
#820=ORIENTED_EDGE('',*,*,#819,.F.);
#821=CARTESIAN_POINT('',(0.,60.6298,0.));
#822=DIRECTION('',(0.,1.,0.));
#823=DIRECTION('',(1.,0.,0.));
#824=AXIS2_PLACEMENT_3D('',#821,#822,#823);
#825=CIRCLE('',#824,10.922);
#826=EDGE_CURVE('P0_E302',#818,#816,#825,.T.);
#827=ORIENTED_EDGE('',*,*,#826,.F.);
#828=EDGE_LOOP('',(#820,#827));
#829=FACE_BOUND('',#828,.T.);
#830=ORIENTED_EDGE('',*,*,#784,.T.);
#831=ORIENTED_EDGE('',*,*,#791,.T.);
#832=EDGE_LOOP('',(#830,#831));
#833=FACE_BOUND('',#832,.T.);
#834=ADVANCED_FACE('P0_F640',(#829,#833),#809,.T.);
#835=CARTESIAN_POINT('',(0.,61.2648,0.));
#836=DIRECTION('',(0.,1.,0.));
#837=DIRECTION('',(0.,0.,1.));
#838=AXIS2_PLACEMENT_3D('',#835,#836,#837);
#839=CYLINDRICAL_SURFACE('',#838,10.922);
#840=CARTESIAN_POINT('',(0.,61.8998,0.));
#841=DIRECTION('',(0.,1.,0.));
#842=DIRECTION('',(1.,0.,0.));
#843=AXIS2_PLACEMENT_3D('',#840,#841,#842);
#844=CIRCLE('',#843,10.922);
#845=CARTESIAN_POINT('',(0.,61.8998,10.922));
#846=VERTEX_POINT('',#845);
#847=CARTESIAN_POINT('',(0.,61.8998,-10.922));
#848=VERTEX_POINT('',#847);
#849=EDGE_CURVE('P0_E428',#846,#848,#844,.T.);
#850=ORIENTED_EDGE('',*,*,#849,.F.);
#851=CARTESIAN_POINT('',(0.,61.8998,0.));
#852=DIRECTION('',(0.,1.,0.));
#853=DIRECTION('',(1.,0.,0.));
#854=AXIS2_PLACEMENT_3D('',#851,#852,#853);
#855=CIRCLE('',#854,10.922);
#856=EDGE_CURVE('P0_E423',#848,#846,#855,.T.);
#857=ORIENTED_EDGE('',*,*,#856,.F.);
#858=DIRECTION('',(0.,-1.,0.));
#859=VECTOR('',#858,1.);
#860=CARTESIAN_POINT('',(0.,61.2648,-10.922));
#861=LINE('',#860,#859);
#862=EDGE_CURVE('P0_E305',#848,#818,#861,.T.);
#863=ORIENTED_EDGE('',*,*,#862,.T.);
#864=ORIENTED_EDGE('',*,*,#826,.T.);
#865=ORIENTED_EDGE('',*,*,#819,.T.);
#866=ORIENTED_EDGE('',*,*,#862,.F.);
#867=EDGE_LOOP('',(#850,#857,#863,#864,#865,#866));
#868=FACE_BOUND('',#867,.T.);
#869=ADVANCED_FACE('P0_F643',(#868),#839,.T.);
#870=CARTESIAN_POINT('',(0.,64.3381999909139,0.));
#871=DIRECTION('',(0.,-1.,0.));
#872=DIRECTION('',(0.,0.,1.));
#873=AXIS2_PLACEMENT_3D('',#870,#871,#872);
#874=CONICAL_SURFACE('',#873,10.2235,0.278987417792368);
#875=CARTESIAN_POINT('',(0.,66.7765999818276,0.));
#876=DIRECTION('',(0.,1.,0.));
#877=DIRECTION('',(1.,0.,0.));
#878=AXIS2_PLACEMENT_3D('',#875,#876,#877);
#879=CIRCLE('',#878,9.525);
#880=CARTESIAN_POINT('',(0.,66.7765999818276,9.525));
#881=VERTEX_POINT('',#880);
#882=CARTESIAN_POINT('',(0.,66.7765999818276,-9.525));
#883=VERTEX_POINT('',#882);
#884=EDGE_CURVE('P0_E316',#881,#883,#879,.T.);
#885=ORIENTED_EDGE('',*,*,#884,.F.);
#886=CARTESIAN_POINT('',(0.,66.7765999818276,0.));
#887=DIRECTION('',(0.,1.,0.));
#888=DIRECTION('',(1.,0.,0.));
#889=AXIS2_PLACEMENT_3D('',#886,#887,#888);
#890=CIRCLE('',#889,9.525);
#891=EDGE_CURVE('P0_E343',#883,#881,#890,.T.);
#892=ORIENTED_EDGE('',*,*,#891,.F.);
#893=DIRECTION('',(0.,-0.961334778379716,-0.275382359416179));
#894=VECTOR('',#893,1.);
#895=CARTESIAN_POINT('',(0.,64.3381999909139,-10.2235));
#896=LINE('',#895,#894);
#897=EDGE_CURVE('P0_E427',#883,#848,#896,.T.);
#898=ORIENTED_EDGE('',*,*,#897,.T.);
#899=ORIENTED_EDGE('',*,*,#856,.T.);
#900=ORIENTED_EDGE('',*,*,#849,.T.);
#901=ORIENTED_EDGE('',*,*,#897,.F.);
#902=EDGE_LOOP('',(#885,#892,#898,#899,#900,#901));
#903=FACE_BOUND('',#902,.T.);
#904=ADVANCED_FACE('P0_F644',(#903),#874,.T.);
#905=CARTESIAN_POINT('',(0.,69.6975999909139,0.));
#906=DIRECTION('',(0.,1.,0.));
#907=DIRECTION('',(0.,0.,1.));
#908=AXIS2_PLACEMENT_3D('',#905,#906,#907);
#909=CYLINDRICAL_SURFACE('',#908,9.525);
#910=CARTESIAN_POINT('',(0.,72.6186,0.));
#911=DIRECTION('',(0.,1.,0.));
#912=DIRECTION('',(1.,0.,0.));
#913=AXIS2_PLACEMENT_3D('',#910,#911,#912);
#914=CIRCLE('',#913,9.525);
#915=CARTESIAN_POINT('',(0.,72.6186,9.525));
#916=VERTEX_POINT('',#915);
#917=CARTESIAN_POINT('',(0.,72.6186,-9.525));
#918=VERTEX_POINT('',#917);
#919=EDGE_CURVE('P0_E312',#916,#918,#914,.T.);
#920=ORIENTED_EDGE('',*,*,#919,.F.);
#921=CARTESIAN_POINT('',(0.,72.6186,0.));
#922=DIRECTION('',(0.,1.,0.));
#923=DIRECTION('',(1.,0.,0.));
#924=AXIS2_PLACEMENT_3D('',#921,#922,#923);
#925=CIRCLE('',#924,9.525);
#926=EDGE_CURVE('P0_E317',#918,#916,#925,.T.);
#927=ORIENTED_EDGE('',*,*,#926,.F.);
#928=DIRECTION('',(0.,-1.,0.));
#929=VECTOR('',#928,1.);
#930=CARTESIAN_POINT('',(0.,69.6975999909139,-9.525));
#931=LINE('',#930,#929);
#932=EDGE_CURVE('P0_E439',#918,#883,#931,.T.);
#933=ORIENTED_EDGE('',*,*,#932,.T.);
#934=ORIENTED_EDGE('',*,*,#891,.T.);
#935=ORIENTED_EDGE('',*,*,#884,.T.);
#936=ORIENTED_EDGE('',*,*,#932,.F.);
#937=EDGE_LOOP('',(#920,#927,#933,#934,#935,#936));
#938=FACE_BOUND('',#937,.T.);
#939=ADVANCED_FACE('P0_F647',(#938),#909,.T.);
#940=CARTESIAN_POINT('',(0.,72.6186,10.922));
#941=DIRECTION('',(0.,-1.,0.));
#942=DIRECTION('',(0.,0.,-1.));
#943=AXIS2_PLACEMENT_3D('',#940,#941,#942);
#944=PLANE('',#943);
#945=CARTESIAN_POINT('',(0.,72.6186,0.));
#946=DIRECTION('',(0.,1.,0.));
#947=DIRECTION('',(1.,0.,0.));
#948=AXIS2_PLACEMENT_3D('',#945,#946,#947);
#949=CIRCLE('',#948,10.922);
#950=CARTESIAN_POINT('',(0.,72.6186,10.922));
#951=VERTEX_POINT('',#950);
#952=CARTESIAN_POINT('',(0.,72.6186,-10.922));
#953=VERTEX_POINT('',#952);
#954=EDGE_CURVE('P0_E387',#951,#953,#949,.T.);
#955=ORIENTED_EDGE('',*,*,#954,.F.);
#956=CARTESIAN_POINT('',(0.,72.6186,0.));
#957=DIRECTION('',(0.,1.,0.));
#958=DIRECTION('',(1.,0.,0.));
#959=AXIS2_PLACEMENT_3D('',#956,#957,#958);
#960=CIRCLE('',#959,10.922);
#961=EDGE_CURVE('P0_E371',#953,#951,#960,.T.);
#962=ORIENTED_EDGE('',*,*,#961,.F.);
#963=EDGE_LOOP('',(#955,#962));
#964=FACE_BOUND('',#963,.T.);
#965=ORIENTED_EDGE('',*,*,#919,.T.);
#966=ORIENTED_EDGE('',*,*,#926,.T.);
#967=EDGE_LOOP('',(#965,#966));
#968=FACE_BOUND('',#967,.T.);
#969=ADVANCED_FACE('P0_F18',(#964,#968),#944,.T.);
#970=CARTESIAN_POINT('',(0.,73.2536,0.));
#971=DIRECTION('',(0.,1.,0.));
#972=DIRECTION('',(0.,0.,1.));
#973=AXIS2_PLACEMENT_3D('',#970,#971,#972);
#974=CYLINDRICAL_SURFACE('',#973,10.922);
#975=CARTESIAN_POINT('',(0.,73.8886,0.));
#976=DIRECTION('',(0.,1.,0.));
#977=DIRECTION('',(1.,0.,0.));
#978=AXIS2_PLACEMENT_3D('',#975,#976,#977);
#979=CIRCLE('',#978,10.922);
#980=CARTESIAN_POINT('',(0.,73.8886,10.922));
#981=VERTEX_POINT('',#980);
#982=CARTESIAN_POINT('',(0.,73.8886,-10.922));
#983=VERTEX_POINT('',#982);
#984=EDGE_CURVE('P0_E519',#981,#983,#979,.T.);
#985=ORIENTED_EDGE('',*,*,#984,.F.);
#986=CARTESIAN_POINT('',(0.,73.8886,0.));
#987=DIRECTION('',(0.,1.,0.));
#988=DIRECTION('',(1.,0.,0.));
#989=AXIS2_PLACEMENT_3D('',#986,#987,#988);
#990=CIRCLE('',#989,10.922);
#991=EDGE_CURVE('P0_E388',#983,#981,#990,.T.);
#992=ORIENTED_EDGE('',*,*,#991,.F.);
#993=DIRECTION('',(0.,-1.,0.));
#994=VECTOR('',#993,1.);
#995=CARTESIAN_POINT('',(0.,73.2536,-10.922));
#996=LINE('',#995,#994);
#997=EDGE_CURVE('P0_E367',#983,#953,#996,.T.);
#998=ORIENTED_EDGE('',*,*,#997,.T.);
#999=ORIENTED_EDGE('',*,*,#961,.T.);
#1000=ORIENTED_EDGE('',*,*,#954,.T.);
#1001=ORIENTED_EDGE('',*,*,#997,.F.);
#1002=EDGE_LOOP('',(#985,#992,#998,#999,#1000,#1001));
#1003=FACE_BOUND('',#1002,.T.);
#1004=ADVANCED_FACE('P0_F703',(#1003),#974,.T.);
#1005=CARTESIAN_POINT('',(0.,76.1492,0.));
#1006=DIRECTION('',(0.,-1.,0.));
#1007=DIRECTION('',(0.,0.,1.));
#1008=AXIS2_PLACEMENT_3D('',#1005,#1006,#1007);
#1009=CONICAL_SURFACE('',#1008,10.2744322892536,0.278987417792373);
#1010=ORIENTED_EDGE('',*,*,#201,.F.);
#1011=ORIENTED_EDGE('',*,*,#194,.F.);
#1012=DIRECTION('',(0.,-0.961334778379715,-0.275382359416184));
#1013=VECTOR('',#1012,1.);
#1014=CARTESIAN_POINT('',(0.,76.1492,-10.2744322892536));
#1015=LINE('',#1014,#1013);
#1016=EDGE_CURVE('P0_E383',#184,#983,#1015,.T.);
#1017=ORIENTED_EDGE('',*,*,#1016,.T.);
#1018=ORIENTED_EDGE('',*,*,#991,.T.);
#1019=ORIENTED_EDGE('',*,*,#984,.T.);
#1020=ORIENTED_EDGE('',*,*,#1016,.F.);
#1021=EDGE_LOOP('',(#1010,#1011,#1017,#1018,#1019,#1020));
#1022=FACE_BOUND('',#1021,.T.);
#1023=ADVANCED_FACE('P0_F618',(#1022),#1009,.T.);
#1024=CLOSED_SHELL('',(#70,#100,#135,#171,#206,#258,#279,#314,#366,#401,#415,#451,#481,#515,
#550,#580,#615,#634,#669,#699,#734,#769,#804,#834,#869,#904,#939,#969,#1004,#1023));
#1025=MANIFOLD_SOLID_BREP('P0_B1',#1024);
#1026=CARTESIAN_POINT('',(0.,40.9575,0.));
#1027=DIRECTION('',(0.,-1.,0.));
#1028=DIRECTION('',(0.,0.,1.));
#1029=AXIS2_PLACEMENT_3D('',#1026,#1027,#1028);
#1030=CONICAL_SURFACE('',#1029,15.5448,0.785398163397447);
#1031=CARTESIAN_POINT('',(0.,40.64,0.));
#1032=DIRECTION('',(0.,1.,0.));
#1033=DIRECTION('',(0.,0.,1.));
#1034=AXIS2_PLACEMENT_3D('',#1031,#1032,#1033);
#1035=CIRCLE('',#1034,15.8623);
#1036=CARTESIAN_POINT('',(0.,40.64,-15.8623));
#1037=VERTEX_POINT('',#1036);
#1038=CARTESIAN_POINT('',(0.,40.64,15.8623));
#1039=VERTEX_POINT('',#1038);
#1040=EDGE_CURVE('P1_E11',#1037,#1039,#1035,.T.);
#1041=ORIENTED_EDGE('',*,*,#1040,.T.);
#1042=CARTESIAN_POINT('',(0.,40.64,0.));
#1043=DIRECTION('',(0.,1.,0.));
#1044=DIRECTION('',(0.,0.,1.));
#1045=AXIS2_PLACEMENT_3D('',#1042,#1043,#1044);
#1046=CIRCLE('',#1045,15.8623);
#1047=EDGE_CURVE('P1_E27',#1039,#1037,#1046,.T.);
#1048=ORIENTED_EDGE('',*,*,#1047,.T.);
#1049=DIRECTION('',(0.,0.707106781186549,0.707106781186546));
#1050=VECTOR('',#1049,1.);
#1051=CARTESIAN_POINT('',(0.,40.9575,-15.5448));
#1052=LINE('',#1051,#1050);
#1053=CARTESIAN_POINT('',(0.,41.275,-15.2273));
#1054=VERTEX_POINT('',#1053);
#1055=EDGE_CURVE('P1_E183',#1037,#1054,#1052,.T.);
#1056=ORIENTED_EDGE('',*,*,#1055,.T.);
#1057=CARTESIAN_POINT('',(0.,41.275,0.));
#1058=DIRECTION('',(0.,-1.,0.));
#1059=DIRECTION('',(0.,0.,1.));
#1060=AXIS2_PLACEMENT_3D('',#1057,#1058,#1059);
#1061=CIRCLE('',#1060,15.2273);
#1062=EDGE_CURVE('P1_E187',#1054,#1054,#1061,.T.);
#1063=ORIENTED_EDGE('',*,*,#1062,.T.);
#1064=ORIENTED_EDGE('',*,*,#1055,.F.);
#1065=EDGE_LOOP('',(#1041,#1048,#1056,#1063,#1064));
#1066=FACE_BOUND('',#1065,.T.);
#1067=ADVANCED_FACE('P1_F16',(#1066),#1030,.T.);
#1068=CARTESIAN_POINT('',(0.,41.275,-15.8623));
#1069=DIRECTION('',(0.,1.,0.));
#1070=DIRECTION('',(1.,0.,0.));
#1071=AXIS2_PLACEMENT_3D('',#1068,#1069,#1070);
#1072=PLANE('',#1071);
#1073=ORIENTED_EDGE('',*,*,#1062,.F.);
#1074=EDGE_LOOP('',(#1073));
#1075=FACE_BOUND('',#1074,.T.);
#1076=CARTESIAN_POINT('',(0.,41.275,0.));
#1077=DIRECTION('',(0.,1.,0.));
#1078=DIRECTION('',(0.,0.,1.));
#1079=AXIS2_PLACEMENT_3D('',#1076,#1077,#1078);
#1080=CIRCLE('',#1079,14.0335);
#1081=CARTESIAN_POINT('',(0.,41.275,-14.0335));
#1082=VERTEX_POINT('',#1081);
#1083=CARTESIAN_POINT('',(0.,41.275,14.0335));
#1084=VERTEX_POINT('',#1083);
#1085=EDGE_CURVE('P1_E188',#1082,#1084,#1080,.T.);
#1086=ORIENTED_EDGE('',*,*,#1085,.F.);
#1087=CARTESIAN_POINT('',(0.,41.275,0.));
#1088=DIRECTION('',(0.,1.,0.));
#1089=DIRECTION('',(0.,0.,1.));
#1090=AXIS2_PLACEMENT_3D('',#1087,#1088,#1089);
#1091=CIRCLE('',#1090,14.0335);
#1092=EDGE_CURVE('P1_E303',#1084,#1082,#1091,.T.);
#1093=ORIENTED_EDGE('',*,*,#1092,.F.);
#1094=EDGE_LOOP('',(#1086,#1093));
#1095=FACE_BOUND('',#1094,.T.);
#1096=ADVANCED_FACE('P1_F398',(#1075,#1095),#1072,.T.);
#1097=CARTESIAN_POINT('',(0.,33.4645,0.));
#1098=DIRECTION('',(0.,-1.,0.));
#1099=DIRECTION('',(0.,0.,-1.));
#1100=AXIS2_PLACEMENT_3D('',#1097,#1098,#1099);
#1101=CYLINDRICAL_SURFACE('',#1100,15.8623);
#1102=CARTESIAN_POINT('',(0.,25.654,0.));
#1103=DIRECTION('',(0.,-1.,0.));
#1104=DIRECTION('',(1.,0.,0.));
#1105=AXIS2_PLACEMENT_3D('',#1102,#1103,#1104);
#1106=CIRCLE('',#1105,15.8623);
#1107=CARTESIAN_POINT('',(0.,25.654,-15.8623));
#1108=VERTEX_POINT('',#1107);
#1109=CARTESIAN_POINT('',(0.,25.654,15.8623));
#1110=VERTEX_POINT('',#1109);
#1111=EDGE_CURVE('P1_E20',#1108,#1110,#1106,.T.);
#1112=ORIENTED_EDGE('',*,*,#1111,.F.);
#1113=CARTESIAN_POINT('',(0.,25.654,0.));
#1114=DIRECTION('',(0.,-1.,0.));
#1115=DIRECTION('',(1.,0.,0.));
#1116=AXIS2_PLACEMENT_3D('',#1113,#1114,#1115);
#1117=CIRCLE('',#1116,15.8623);
#1118=EDGE_CURVE('P1_E326',#1110,#1108,#1117,.T.);
#1119=ORIENTED_EDGE('',*,*,#1118,.F.);
#1120=DIRECTION('',(0.,1.,0.));
#1121=VECTOR('',#1120,1.);
#1122=CARTESIAN_POINT('',(0.,33.4645,15.8623));
#1123=LINE('',#1122,#1121);
#1124=EDGE_CURVE('P1_E503',#1110,#1039,#1123,.T.);
#1125=ORIENTED_EDGE('',*,*,#1124,.T.);
#1126=ORIENTED_EDGE('',*,*,#1040,.F.);
#1127=ORIENTED_EDGE('',*,*,#1047,.F.);
#1128=ORIENTED_EDGE('',*,*,#1124,.F.);
#1129=EDGE_LOOP('',(#1112,#1119,#1125,#1126,#1127,#1128));
#1130=FACE_BOUND('',#1129,.T.);
#1131=ADVANCED_FACE('P1_F392',(#1130),#1101,.T.);
#1132=CARTESIAN_POINT('',(0.,4.953,0.));
#1133=DIRECTION('',(0.,-1.,0.));
#1134=DIRECTION('',(0.,0.,-1.));
#1135=AXIS2_PLACEMENT_3D('',#1132,#1133,#1134);
#1136=TOROIDAL_SURFACE('',#1135,12.446,0.254);
#1137=CARTESIAN_POINT('',(0.,5.207,0.));
#1138=DIRECTION('',(0.,1.,0.));
#1139=DIRECTION('',(0.,0.,1.));
#1140=AXIS2_PLACEMENT_3D('',#1137,#1138,#1139);
#1141=CIRCLE('',#1140,12.446);
#1142=CARTESIAN_POINT('',(0.,5.207,-12.446));
#1143=VERTEX_POINT('',#1142);
#1144=CARTESIAN_POINT('',(0.,5.207,12.446));
#1145=VERTEX_POINT('',#1144);
#1146=EDGE_CURVE('P1_E509',#1143,#1145,#1141,.T.);
#1147=ORIENTED_EDGE('',*,*,#1146,.T.);
#1148=CARTESIAN_POINT('',(0.,4.953,12.446));
#1149=DIRECTION('',(-1.,0.,0.));
#1150=DIRECTION('',(0.,0.,1.));
#1151=AXIS2_PLACEMENT_3D('',#1148,#1149,#1150);
#1152=CIRCLE('',#1151,0.254);
#1153=CARTESIAN_POINT('',(0.,4.953,12.192));
#1154=VERTEX_POINT('',#1153);
#1155=EDGE_CURVE('P1_E144',#1145,#1154,#1152,.T.);
#1156=ORIENTED_EDGE('',*,*,#1155,.T.);
#1157=CARTESIAN_POINT('',(0.,4.953,0.));
#1158=DIRECTION('',(0.,-1.,0.));
#1159=DIRECTION('',(0.,0.,1.));
#1160=AXIS2_PLACEMENT_3D('',#1157,#1158,#1159);
#1161=CIRCLE('',#1160,12.192);
#1162=CARTESIAN_POINT('',(0.,4.953,-12.192));
#1163=VERTEX_POINT('',#1162);
#1164=EDGE_CURVE('P1_E140',#1154,#1163,#1161,.T.);
#1165=ORIENTED_EDGE('',*,*,#1164,.T.);
#1166=CARTESIAN_POINT('',(0.,4.953,0.));
#1167=DIRECTION('',(0.,-1.,0.));
#1168=DIRECTION('',(0.,0.,1.));
#1169=AXIS2_PLACEMENT_3D('',#1166,#1167,#1168);
#1170=CIRCLE('',#1169,12.192);
#1171=EDGE_CURVE('P1_E143',#1163,#1154,#1170,.T.);
#1172=ORIENTED_EDGE('',*,*,#1171,.T.);
#1173=ORIENTED_EDGE('',*,*,#1155,.F.);
#1174=CARTESIAN_POINT('',(0.,5.207,0.));
#1175=DIRECTION('',(0.,1.,0.));
#1176=DIRECTION('',(0.,0.,1.));
#1177=AXIS2_PLACEMENT_3D('',#1174,#1175,#1176);
#1178=CIRCLE('',#1177,12.446);
#1179=EDGE_CURVE('P1_E153',#1145,#1143,#1178,.T.);
#1180=ORIENTED_EDGE('',*,*,#1179,.T.);
#1181=EDGE_LOOP('',(#1147,#1156,#1165,#1172,#1173,#1180));
#1182=FACE_BOUND('',#1181,.T.);
#1183=ADVANCED_FACE('P1_F18',(#1182),#1136,.T.);
#1184=CARTESIAN_POINT('',(0.,2.6035,0.));
#1185=DIRECTION('',(0.,-1.,0.));
#1186=DIRECTION('',(0.,0.,-1.));
#1187=AXIS2_PLACEMENT_3D('',#1184,#1185,#1186);
#1188=CYLINDRICAL_SURFACE('',#1187,12.192);
#1189=CARTESIAN_POINT('',(0.,0.254,0.));
#1190=DIRECTION('',(0.,1.,0.));
#1191=DIRECTION('',(0.,0.,1.));
#1192=AXIS2_PLACEMENT_3D('',#1189,#1190,#1191);
#1193=CIRCLE('',#1192,12.192);
#1194=CARTESIAN_POINT('',(0.,0.254,-12.192));
#1195=VERTEX_POINT('',#1194);
#1196=CARTESIAN_POINT('',(0.,0.254,12.192));
#1197=VERTEX_POINT('',#1196);
#1198=EDGE_CURVE('P1_E163',#1195,#1197,#1193,.T.);
#1199=ORIENTED_EDGE('',*,*,#1198,.F.);
#1200=CARTESIAN_POINT('',(0.,0.254,0.));
#1201=DIRECTION('',(0.,1.,0.));
#1202=DIRECTION('',(0.,0.,1.));
#1203=AXIS2_PLACEMENT_3D('',#1200,#1201,#1202);
#1204=CIRCLE('',#1203,12.192);
#1205=EDGE_CURVE('P1_E177',#1197,#1195,#1204,.T.);
#1206=ORIENTED_EDGE('',*,*,#1205,.F.);
#1207=DIRECTION('',(0.,1.,0.));
#1208=VECTOR('',#1207,1.);
#1209=CARTESIAN_POINT('',(0.,2.6035,12.192));
#1210=LINE('',#1209,#1208);
#1211=EDGE_CURVE('P1_E151',#1197,#1154,#1210,.T.);
#1212=ORIENTED_EDGE('',*,*,#1211,.T.);
#1213=ORIENTED_EDGE('',*,*,#1171,.F.);
#1214=ORIENTED_EDGE('',*,*,#1164,.F.);
#1215=ORIENTED_EDGE('',*,*,#1211,.F.);
#1216=EDGE_LOOP('',(#1199,#1206,#1212,#1213,#1214,#1215));
#1217=FACE_BOUND('',#1216,.T.);
#1218=ADVANCED_FACE('P1_F150',(#1217),#1188,.F.);
#1219=CARTESIAN_POINT('',(0.,5.207,-13.7795));
#1220=DIRECTION('',(0.,1.,0.));
#1221=DIRECTION('',(1.,0.,0.));
#1222=AXIS2_PLACEMENT_3D('',#1219,#1220,#1221);
#1223=PLANE('',#1222);
#1224=CARTESIAN_POINT('',(0.,5.207,0.));
#1225=DIRECTION('',(0.,-1.,0.));
#1226=DIRECTION('',(1.,0.,0.));
#1227=AXIS2_PLACEMENT_3D('',#1224,#1225,#1226);
#1228=CIRCLE('',#1227,13.7795);
#1229=CARTESIAN_POINT('',(0.,5.207,-13.7795));
#1230=VERTEX_POINT('',#1229);
#1231=CARTESIAN_POINT('',(0.,5.207,13.7795));
#1232=VERTEX_POINT('',#1231);
#1233=EDGE_CURVE('P1_E124',#1230,#1232,#1228,.T.);
#1234=ORIENTED_EDGE('',*,*,#1233,.F.);
#1235=CARTESIAN_POINT('',(0.,5.207,0.));
#1236=DIRECTION('',(0.,-1.,0.));
#1237=DIRECTION('',(1.,0.,0.));
#1238=AXIS2_PLACEMENT_3D('',#1235,#1236,#1237);
#1239=CIRCLE('',#1238,13.7795);
#1240=EDGE_CURVE('P1_E131',#1232,#1230,#1239,.T.);
#1241=ORIENTED_EDGE('',*,*,#1240,.F.);
#1242=EDGE_LOOP('',(#1234,#1241));
#1243=FACE_BOUND('',#1242,.T.);
#1244=ORIENTED_EDGE('',*,*,#1146,.F.);
#1245=ORIENTED_EDGE('',*,*,#1179,.F.);
#1246=EDGE_LOOP('',(#1244,#1245));
#1247=FACE_BOUND('',#1246,.T.);
#1248=ADVANCED_FACE('P1_F359',(#1243,#1247),#1223,.T.);
#1249=CARTESIAN_POINT('',(0.,0.254,0.));
#1250=DIRECTION('',(0.,-1.,0.));
#1251=DIRECTION('',(0.,0.,-1.));
#1252=AXIS2_PLACEMENT_3D('',#1249,#1250,#1251);
#1253=TOROIDAL_SURFACE('',#1252,12.446,0.254);
#1254=ORIENTED_EDGE('',*,*,#1198,.T.);
#1255=CARTESIAN_POINT('',(0.,0.254,12.446));
#1256=DIRECTION('',(-1.,0.,0.));
#1257=DIRECTION('',(0.,0.,1.));
#1258=AXIS2_PLACEMENT_3D('',#1255,#1256,#1257);
#1259=CIRCLE('',#1258,0.254);
#1260=CARTESIAN_POINT('',(0.,0.,12.446));
#1261=VERTEX_POINT('',#1260);
#1262=EDGE_CURVE('P1_E167',#1197,#1261,#1259,.T.);
#1263=ORIENTED_EDGE('',*,*,#1262,.T.);
#1264=CARTESIAN_POINT('',(0.,0.,0.));
#1265=DIRECTION('',(0.,-1.,0.));
#1266=DIRECTION('',(0.,0.,1.));
#1267=AXIS2_PLACEMENT_3D('',#1264,#1265,#1266);
#1268=CIRCLE('',#1267,12.446);
#1269=CARTESIAN_POINT('',(0.,0.,-12.446));
#1270=VERTEX_POINT('',#1269);
#1271=EDGE_CURVE('P1_E176',#1261,#1270,#1268,.T.);
#1272=ORIENTED_EDGE('',*,*,#1271,.T.);
#1273=CARTESIAN_POINT('',(0.,0.,0.));
#1274=DIRECTION('',(0.,-1.,0.));
#1275=DIRECTION('',(0.,0.,1.));
#1276=AXIS2_PLACEMENT_3D('',#1273,#1274,#1275);
#1277=CIRCLE('',#1276,12.446);
#1278=EDGE_CURVE('P1_E172',#1270,#1261,#1277,.T.);
#1279=ORIENTED_EDGE('',*,*,#1278,.T.);
#1280=ORIENTED_EDGE('',*,*,#1262,.F.);
#1281=ORIENTED_EDGE('',*,*,#1205,.T.);
#1282=EDGE_LOOP('',(#1254,#1263,#1272,#1279,#1280,#1281));
#1283=FACE_BOUND('',#1282,.T.);
#1284=ADVANCED_FACE('P1_F353',(#1283),#1253,.T.);
#1285=CARTESIAN_POINT('',(0.,0.,-12.192));
#1286=DIRECTION('',(0.,-1.,0.));
#1287=DIRECTION('',(0.,0.,-1.));
#1288=AXIS2_PLACEMENT_3D('',#1285,#1286,#1287);
#1289=PLANE('',#1288);
#1290=CARTESIAN_POINT('',(0.,0.,0.));
#1291=DIRECTION('',(0.,1.,0.));
#1292=DIRECTION('',(0.,0.,1.));
#1293=AXIS2_PLACEMENT_3D('',#1290,#1291,#1292);
#1294=CIRCLE('',#1293,14.8082);
#1295=CARTESIAN_POINT('',(0.,0.,-14.8082));
#1296=VERTEX_POINT('',#1295);
#1297=CARTESIAN_POINT('',(0.,0.,14.8082));
#1298=VERTEX_POINT('',#1297);
#1299=EDGE_CURVE('P1_E230',#1296,#1298,#1294,.T.);
#1300=ORIENTED_EDGE('',*,*,#1299,.F.);
#1301=CARTESIAN_POINT('',(0.,0.,0.));
#1302=DIRECTION('',(0.,1.,0.));
#1303=DIRECTION('',(0.,0.,1.));
#1304=AXIS2_PLACEMENT_3D('',#1301,#1302,#1303);
#1305=CIRCLE('',#1304,14.8082);
#1306=EDGE_CURVE('P1_E257',#1298,#1296,#1305,.T.);
#1307=ORIENTED_EDGE('',*,*,#1306,.F.);
#1308=EDGE_LOOP('',(#1300,#1307));
#1309=FACE_BOUND('',#1308,.T.);
#1310=ORIENTED_EDGE('',*,*,#1278,.F.);
#1311=ORIENTED_EDGE('',*,*,#1271,.F.);
#1312=EDGE_LOOP('',(#1310,#1311));
#1313=FACE_BOUND('',#1312,.T.);
#1314=ADVANCED_FACE('P1_F358',(#1309,#1313),#1289,.T.);
#1315=CARTESIAN_POINT('',(0.,0.254,0.));
#1316=DIRECTION('',(0.,-1.,0.));
#1317=DIRECTION('',(0.,0.,-1.));
#1318=AXIS2_PLACEMENT_3D('',#1315,#1316,#1317);
#1319=TOROIDAL_SURFACE('',#1318,14.8082,0.254);
#1320=ORIENTED_EDGE('',*,*,#1299,.T.);
#1321=CARTESIAN_POINT('',(0.,0.254,14.8082));
#1322=DIRECTION('',(-1.,0.,0.));
#1323=DIRECTION('',(0.,0.,1.));
#1324=AXIS2_PLACEMENT_3D('',#1321,#1322,#1323);
#1325=CIRCLE('',#1324,0.254);
#1326=CARTESIAN_POINT('',(0.,0.254,15.0622));
#1327=VERTEX_POINT('',#1326);
#1328=EDGE_CURVE('P1_E181',#1298,#1327,#1325,.T.);
#1329=ORIENTED_EDGE('',*,*,#1328,.T.);
#1330=CARTESIAN_POINT('',(0.,0.254,0.));
#1331=DIRECTION('',(0.,-1.,0.));
#1332=DIRECTION('',(0.,0.,1.));
#1333=AXIS2_PLACEMENT_3D('',#1330,#1331,#1332);
#1334=CIRCLE('',#1333,15.0622);
#1335=CARTESIAN_POINT('',(0.,0.254,-15.0622));
#1336=VERTEX_POINT('',#1335);
#1337=EDGE_CURVE('P1_E178',#1327,#1336,#1334,.T.);
#1338=ORIENTED_EDGE('',*,*,#1337,.T.);
#1339=CARTESIAN_POINT('',(0.,0.254,0.));
#1340=DIRECTION('',(0.,-1.,0.));
#1341=DIRECTION('',(0.,0.,1.));
#1342=AXIS2_PLACEMENT_3D('',#1339,#1340,#1341);
#1343=CIRCLE('',#1342,15.0622);
#1344=EDGE_CURVE('P1_E182',#1336,#1327,#1343,.T.);
#1345=ORIENTED_EDGE('',*,*,#1344,.T.);
#1346=ORIENTED_EDGE('',*,*,#1328,.F.);
#1347=ORIENTED_EDGE('',*,*,#1306,.T.);
#1348=EDGE_LOOP('',(#1320,#1329,#1338,#1345,#1346,#1347));
#1349=FACE_BOUND('',#1348,.T.);
#1350=ADVANCED_FACE('P1_F346',(#1349),#1319,.T.);
#1351=CARTESIAN_POINT('',(0.,12.42695,0.));
#1352=DIRECTION('',(0.,-1.,0.));
#1353=DIRECTION('',(0.,0.,-1.));
#1354=AXIS2_PLACEMENT_3D('',#1351,#1352,#1353);
#1355=CYLINDRICAL_SURFACE('',#1354,15.0622);
#1356=ORIENTED_EDGE('',*,*,#1344,.F.);
#1357=ORIENTED_EDGE('',*,*,#1337,.F.);
#1358=DIRECTION('',(0.,1.,0.));
#1359=VECTOR('',#1358,1.);
#1360=CARTESIAN_POINT('',(0.,12.42695,15.0622));
#1361=LINE('',#1360,#1359);
#1362=CARTESIAN_POINT('',(0.,24.8539,15.0622));
#1363=VERTEX_POINT('',#1362);
#1364=EDGE_CURVE('P1_E264',#1327,#1363,#1361,.T.);
#1365=ORIENTED_EDGE('',*,*,#1364,.T.);
#1366=CARTESIAN_POINT('',(0.,24.8539,0.));
#1367=DIRECTION('',(0.,-1.,0.));
#1368=DIRECTION('',(1.,0.,0.));
#1369=AXIS2_PLACEMENT_3D('',#1366,#1367,#1368);
#1370=CIRCLE('',#1369,15.0622);
#1371=CARTESIAN_POINT('',(0.,24.8539,-15.0622));
#1372=VERTEX_POINT('',#1371);
#1373=EDGE_CURVE('P1_E272',#1363,#1372,#1370,.T.);
#1374=ORIENTED_EDGE('',*,*,#1373,.T.);
#1375=CARTESIAN_POINT('',(0.,24.8539,0.));
#1376=DIRECTION('',(0.,-1.,0.));
#1377=DIRECTION('',(1.,0.,0.));
#1378=AXIS2_PLACEMENT_3D('',#1375,#1376,#1377);
#1379=CIRCLE('',#1378,15.0622);
#1380=EDGE_CURVE('P1_E191',#1372,#1363,#1379,.T.);
#1381=ORIENTED_EDGE('',*,*,#1380,.T.);
#1382=ORIENTED_EDGE('',*,*,#1364,.F.);
#1383=EDGE_LOOP('',(#1356,#1357,#1365,#1374,#1381,#1382));
#1384=FACE_BOUND('',#1383,.T.);
#1385=ADVANCED_FACE('P1_F340',(#1384),#1355,.T.);
#1386=CARTESIAN_POINT('',(0.,41.021,0.));
#1387=DIRECTION('',(0.,-1.,0.));
#1388=DIRECTION('',(0.,0.,-1.));
#1389=AXIS2_PLACEMENT_3D('',#1386,#1387,#1388);
#1390=TOROIDAL_SURFACE('',#1389,14.0335,0.254);
#1391=ORIENTED_EDGE('',*,*,#1085,.T.);
#1392=CARTESIAN_POINT('',(0.,41.021,14.0335));
#1393=DIRECTION('',(-1.,0.,0.));
#1394=DIRECTION('',(0.,0.,1.));
#1395=AXIS2_PLACEMENT_3D('',#1392,#1393,#1394);
#1396=CIRCLE('',#1395,0.254);
#1397=CARTESIAN_POINT('',(0.,41.021,13.7795));
#1398=VERTEX_POINT('',#1397);
#1399=EDGE_CURVE('P1_E192',#1084,#1398,#1396,.T.);
#1400=ORIENTED_EDGE('',*,*,#1399,.T.);
#1401=CARTESIAN_POINT('',(0.,41.021,0.));
#1402=DIRECTION('',(0.,-1.,0.));
#1403=DIRECTION('',(0.,0.,1.));
#1404=AXIS2_PLACEMENT_3D('',#1401,#1402,#1403);
#1405=CIRCLE('',#1404,13.7795);
#1406=CARTESIAN_POINT('',(0.,41.021,-13.7795));
#1407=VERTEX_POINT('',#1406);
#1408=EDGE_CURVE('P1_E291',#1398,#1407,#1405,.T.);
#1409=ORIENTED_EDGE('',*,*,#1408,.T.);
#1410=CARTESIAN_POINT('',(0.,41.021,0.));
#1411=DIRECTION('',(0.,-1.,0.));
#1412=DIRECTION('',(0.,0.,1.));
#1413=AXIS2_PLACEMENT_3D('',#1410,#1411,#1412);
#1414=CIRCLE('',#1413,13.7795);
#1415=EDGE_CURVE('P1_E297',#1407,#1398,#1414,.T.);
#1416=ORIENTED_EDGE('',*,*,#1415,.T.);
#1417=ORIENTED_EDGE('',*,*,#1399,.F.);
#1418=ORIENTED_EDGE('',*,*,#1092,.T.);
#1419=EDGE_LOOP('',(#1391,#1400,#1409,#1416,#1417,#1418));
#1420=FACE_BOUND('',#1419,.T.);
#1421=ADVANCED_FACE('P1_F345',(#1420),#1390,.T.);
#1422=CARTESIAN_POINT('',(0.,23.241,0.));
#1423=DIRECTION('',(0.,-1.,0.));
#1424=DIRECTION('',(0.,0.,-1.));
#1425=AXIS2_PLACEMENT_3D('',#1422,#1423,#1424);
#1426=CYLINDRICAL_SURFACE('',#1425,13.7795);
#1427=ORIENTED_EDGE('',*,*,#1233,.T.);
#1428=DIRECTION('',(0.,1.,0.));
#1429=VECTOR('',#1428,1.);
#1430=CARTESIAN_POINT('',(0.,23.241,13.7795));
#1431=LINE('',#1430,#1429);
#1432=EDGE_CURVE('P1_E170',#1232,#1398,#1431,.T.);
#1433=ORIENTED_EDGE('',*,*,#1432,.T.);
#1434=ORIENTED_EDGE('',*,*,#1415,.F.);
#1435=ORIENTED_EDGE('',*,*,#1408,.F.);
#1436=ORIENTED_EDGE('',*,*,#1432,.F.);
#1437=ORIENTED_EDGE('',*,*,#1240,.T.);
#1438=EDGE_LOOP('',(#1427,#1433,#1434,#1435,#1436,#1437));
#1439=FACE_BOUND('',#1438,.T.);
#1440=ADVANCED_FACE('P1_F374',(#1439),#1426,.F.);
#1441=CARTESIAN_POINT('',(0.,25.25395,0.));
#1442=DIRECTION('',(0.,1.,0.));
#1443=DIRECTION('',(0.,0.,-1.));
#1444=AXIS2_PLACEMENT_3D('',#1441,#1442,#1443);
#1445=CONICAL_SURFACE('',#1444,15.46225,0.785398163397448);
#1446=ORIENTED_EDGE('',*,*,#1380,.F.);
#1447=ORIENTED_EDGE('',*,*,#1373,.F.);
#1448=DIRECTION('',(0.,0.707106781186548,0.707106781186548));
#1449=VECTOR('',#1448,1.);
#1450=CARTESIAN_POINT('',(0.,25.25395,15.46225));
#1451=LINE('',#1450,#1449);
#1452=EDGE_CURVE('P1_E171',#1363,#1110,#1451,.T.);
#1453=ORIENTED_EDGE('',*,*,#1452,.T.);
#1454=ORIENTED_EDGE('',*,*,#1118,.T.);
#1455=ORIENTED_EDGE('',*,*,#1111,.T.);
#1456=ORIENTED_EDGE('',*,*,#1452,.F.);
#1457=EDGE_LOOP('',(#1446,#1447,#1453,#1454,#1455,#1456));
#1458=FACE_BOUND('',#1457,.T.);
#1459=ADVANCED_FACE('P1_F379',(#1458),#1445,.T.);
#1460=CLOSED_SHELL('',(#1067,#1096,#1131,#1183,#1218,#1248,#1284,#1314,#1350,#1385,#1421,#1440,#1459));
#1461=MANIFOLD_SOLID_BREP('P1_B1',#1460);
#1462=CARTESIAN_POINT('',(0.,20.9931,0.));
#1463=DIRECTION('',(0.,1.,0.));
#1464=DIRECTION('',(0.,0.,1.));
#1465=AXIS2_PLACEMENT_3D('',#1462,#1463,#1464);
#1466=CYLINDRICAL_SURFACE('',#1465,7.9248);
#1467=CARTESIAN_POINT('',(0.,23.9776,0.));
#1468=DIRECTION('',(0.,1.,0.));
#1469=DIRECTION('',(1.,0.,0.));
#1470=AXIS2_PLACEMENT_3D('',#1467,#1468,#1469);
#1471=CIRCLE('',#1470,7.9248);
#1472=CARTESIAN_POINT('',(0.,23.9776,7.9248));
#1473=VERTEX_POINT('',#1472);
#1474=CARTESIAN_POINT('',(0.,23.9776,-7.9248));
#1475=VERTEX_POINT('',#1474);
#1476=EDGE_CURVE('P2_E11',#1473,#1475,#1471,.T.);
#1477=ORIENTED_EDGE('',*,*,#1476,.T.);
#1478=DIRECTION('',(0.,-1.,0.));
#1479=VECTOR('',#1478,1.);
#1480=CARTESIAN_POINT('',(0.,20.9931,-7.9248));
#1481=LINE('',#1480,#1479);
#1482=CARTESIAN_POINT('',(0.,18.0086,-7.9248));
#1483=VERTEX_POINT('',#1482);
#1484=EDGE_CURVE('P2_E27',#1475,#1483,#1481,.T.);
#1485=ORIENTED_EDGE('',*,*,#1484,.T.);
#1486=CARTESIAN_POINT('',(0.,18.0086,0.));
#1487=DIRECTION('',(0.,1.,0.));
#1488=DIRECTION('',(1.,0.,0.));
#1489=AXIS2_PLACEMENT_3D('',#1486,#1487,#1488);
#1490=CIRCLE('',#1489,7.9248);
#1491=CARTESIAN_POINT('',(0.,18.0086,7.9248));
#1492=VERTEX_POINT('',#1491);
#1493=EDGE_CURVE('P2_E81',#1492,#1483,#1490,.T.);
#1494=ORIENTED_EDGE('',*,*,#1493,.F.);
#1495=CARTESIAN_POINT('',(0.,18.0086,0.));
#1496=DIRECTION('',(0.,1.,0.));
#1497=DIRECTION('',(1.,0.,0.));
#1498=AXIS2_PLACEMENT_3D('',#1495,#1496,#1497);
#1499=CIRCLE('',#1498,7.9248);
#1500=EDGE_CURVE('P2_E78',#1483,#1492,#1499,.T.);
#1501=ORIENTED_EDGE('',*,*,#1500,.F.);
#1502=ORIENTED_EDGE('',*,*,#1484,.F.);
#1503=CARTESIAN_POINT('',(0.,23.9776,0.));
#1504=DIRECTION('',(0.,1.,0.));
#1505=DIRECTION('',(1.,0.,0.));
#1506=AXIS2_PLACEMENT_3D('',#1503,#1504,#1505);
#1507=CIRCLE('',#1506,7.9248);
#1508=EDGE_CURVE('P2_E20',#1475,#1473,#1507,.T.);
#1509=ORIENTED_EDGE('',*,*,#1508,.T.);
#1510=EDGE_LOOP('',(#1477,#1485,#1494,#1501,#1502,#1509));
#1511=FACE_BOUND('',#1510,.T.);
#1512=ADVANCED_FACE('P2_F16',(#1511),#1466,.F.);
#1513=CARTESIAN_POINT('',(0.,18.0086,10.668));
#1514=DIRECTION('',(0.,-1.,0.));
#1515=DIRECTION('',(0.,0.,-1.));
#1516=AXIS2_PLACEMENT_3D('',#1513,#1514,#1515);
#1517=PLANE('',#1516);
#1518=CARTESIAN_POINT('',(0.,18.0086,0.));
#1519=DIRECTION('',(0.,1.,0.));
#1520=DIRECTION('',(1.,0.,0.));
#1521=AXIS2_PLACEMENT_3D('',#1518,#1519,#1520);
#1522=CIRCLE('',#1521,10.668);
#1523=CARTESIAN_POINT('',(0.,18.0086,10.668));
#1524=VERTEX_POINT('',#1523);
#1525=CARTESIAN_POINT('',(0.,18.0086,-10.668));
#1526=VERTEX_POINT('',#1525);
#1527=EDGE_CURVE('P2_E69',#1524,#1526,#1522,.T.);
#1528=ORIENTED_EDGE('',*,*,#1527,.F.);
#1529=CARTESIAN_POINT('',(0.,18.0086,0.));
#1530=DIRECTION('',(0.,1.,0.));
#1531=DIRECTION('',(1.,0.,0.));
#1532=AXIS2_PLACEMENT_3D('',#1529,#1530,#1531);
#1533=CIRCLE('',#1532,10.668);
#1534=EDGE_CURVE('P2_E85',#1526,#1524,#1533,.T.);
#1535=ORIENTED_EDGE('',*,*,#1534,.F.);
#1536=EDGE_LOOP('',(#1528,#1535));
#1537=FACE_BOUND('',#1536,.T.);
#1538=ORIENTED_EDGE('',*,*,#1493,.T.);
#1539=ORIENTED_EDGE('',*,*,#1500,.T.);
#1540=EDGE_LOOP('',(#1538,#1539));
#1541=FACE_BOUND('',#1540,.T.);
#1542=ADVANCED_FACE('P2_F99',(#1537,#1541),#1517,.T.);
#1543=CARTESIAN_POINT('',(0.,20.9931,0.));
#1544=DIRECTION('',(0.,1.,0.));
#1545=DIRECTION('',(0.,0.,1.));
#1546=AXIS2_PLACEMENT_3D('',#1543,#1544,#1545);
#1547=CYLINDRICAL_SURFACE('',#1546,10.668);
#1548=CARTESIAN_POINT('',(0.,23.9776,0.));
#1549=DIRECTION('',(0.,1.,0.));
#1550=DIRECTION('',(1.,0.,0.));
#1551=AXIS2_PLACEMENT_3D('',#1548,#1549,#1550);
#1552=CIRCLE('',#1551,10.668);
#1553=CARTESIAN_POINT('',(0.,23.9776,10.668));
#1554=VERTEX_POINT('',#1553);
#1555=CARTESIAN_POINT('',(0.,23.9776,-10.668));
#1556=VERTEX_POINT('',#1555);
#1557=EDGE_CURVE('P2_E61',#1554,#1556,#1552,.T.);
#1558=ORIENTED_EDGE('',*,*,#1557,.F.);
#1559=CARTESIAN_POINT('',(0.,23.9776,0.));
#1560=DIRECTION('',(0.,1.,0.));
#1561=DIRECTION('',(1.,0.,0.));
#1562=AXIS2_PLACEMENT_3D('',#1559,#1560,#1561);
#1563=CIRCLE('',#1562,10.668);
#1564=EDGE_CURVE('P2_E65',#1556,#1554,#1563,.T.);
#1565=ORIENTED_EDGE('',*,*,#1564,.F.);
#1566=DIRECTION('',(0.,-1.,0.));
#1567=VECTOR('',#1566,1.);
#1568=CARTESIAN_POINT('',(0.,20.9931,-10.668));
#1569=LINE('',#1568,#1567);
#1570=EDGE_CURVE('P2_E66',#1556,#1526,#1569,.T.);
#1571=ORIENTED_EDGE('',*,*,#1570,.T.);
#1572=ORIENTED_EDGE('',*,*,#1534,.T.);
#1573=ORIENTED_EDGE('',*,*,#1527,.T.);
#1574=ORIENTED_EDGE('',*,*,#1570,.F.);
#1575=EDGE_LOOP('',(#1558,#1565,#1571,#1572,#1573,#1574));
#1576=FACE_BOUND('',#1575,.T.);
#1577=ADVANCED_FACE('P2_F63',(#1576),#1547,.T.);
#1578=CARTESIAN_POINT('',(0.,23.9776,7.9248));
#1579=DIRECTION('',(0.,1.,0.));
#1580=DIRECTION('',(1.,0.,0.));
#1581=AXIS2_PLACEMENT_3D('',#1578,#1579,#1580);
#1582=PLANE('',#1581);
#1583=ORIENTED_EDGE('',*,*,#1557,.T.);
#1584=ORIENTED_EDGE('',*,*,#1564,.T.);
#1585=EDGE_LOOP('',(#1583,#1584));
#1586=FACE_BOUND('',#1585,.T.);
#1587=ORIENTED_EDGE('',*,*,#1476,.F.);
#1588=ORIENTED_EDGE('',*,*,#1508,.F.);
#1589=EDGE_LOOP('',(#1587,#1588));
#1590=FACE_BOUND('',#1589,.T.);
#1591=ADVANCED_FACE('P2_F18',(#1586,#1590),#1582,.T.);
#1592=CLOSED_SHELL('',(#1512,#1542,#1577,#1591));
#1593=MANIFOLD_SOLID_BREP('P2_B1',#1592);
#1594=CARTESIAN_POINT('',(0.,47.599216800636,-10.795));
#1595=DIRECTION('',(0.,-1.,0.));
#1596=DIRECTION('',(0.,0.,-1.));
#1597=AXIS2_PLACEMENT_3D('',#1594,#1595,#1596);
#1598=PLANE('',#1597);
#1599=CARTESIAN_POINT('',(0.,47.599216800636,0.));
#1600=DIRECTION('',(0.,-1.,0.));
#1601=DIRECTION('',(1.,0.,0.));
#1602=AXIS2_PLACEMENT_3D('',#1599,#1600,#1601);
#1603=CIRCLE('',#1602,16.129);
#1604=CARTESIAN_POINT('',(0.,47.599216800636,-16.129));
#1605=VERTEX_POINT('',#1604);
#1606=CARTESIAN_POINT('',(0.,47.599216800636,16.129));
#1607=VERTEX_POINT('',#1606);
#1608=EDGE_CURVE('P3_E10',#1605,#1607,#1603,.T.);
#1609=ORIENTED_EDGE('',*,*,#1608,.T.);
#1610=CARTESIAN_POINT('',(0.,47.599216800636,0.));
#1611=DIRECTION('',(0.,-1.,0.));
#1612=DIRECTION('',(1.,0.,0.));
#1613=AXIS2_PLACEMENT_3D('',#1610,#1611,#1612);
#1614=CIRCLE('',#1613,16.129);
#1615=EDGE_CURVE('P3_E25',#1607,#1605,#1614,.T.);
#1616=ORIENTED_EDGE('',*,*,#1615,.T.);
#1617=EDGE_LOOP('',(#1609,#1616));
#1618=FACE_BOUND('',#1617,.T.);
#1619=CARTESIAN_POINT('',(0.,47.599216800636,0.));
#1620=DIRECTION('',(0.,-1.,0.));
#1621=DIRECTION('',(1.,0.,0.));
#1622=AXIS2_PLACEMENT_3D('',#1619,#1620,#1621);
#1623=CIRCLE('',#1622,10.795);
#1624=CARTESIAN_POINT('',(0.,47.599216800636,-10.795));
#1625=VERTEX_POINT('',#1624);
#1626=CARTESIAN_POINT('',(0.,47.599216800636,10.795));
#1627=VERTEX_POINT('',#1626);
#1628=EDGE_CURVE('P3_E152',#1625,#1627,#1623,.T.);
#1629=ORIENTED_EDGE('',*,*,#1628,.F.);
#1630=CARTESIAN_POINT('',(0.,47.599216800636,0.));
#1631=DIRECTION('',(0.,-1.,0.));
#1632=DIRECTION('',(1.,0.,0.));
#1633=AXIS2_PLACEMENT_3D('',#1630,#1631,#1632);
#1634=CIRCLE('',#1633,10.795);
#1635=EDGE_CURVE('P3_E108',#1627,#1625,#1634,.T.);
#1636=ORIENTED_EDGE('',*,*,#1635,.F.);
#1637=EDGE_LOOP('',(#1629,#1636));
#1638=FACE_BOUND('',#1637,.T.);
#1639=ADVANCED_FACE('P3_F15',(#1618,#1638),#1598,.T.);
#1640=CARTESIAN_POINT('',(0.,48.234216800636,0.));
#1641=DIRECTION('',(0.,-1.,0.));
#1642=DIRECTION('',(0.,0.,-1.));
#1643=AXIS2_PLACEMENT_3D('',#1640,#1641,#1642);
#1644=CYLINDRICAL_SURFACE('',#1643,10.795);
#1645=ORIENTED_EDGE('',*,*,#1628,.T.);
#1646=DIRECTION('',(0.,1.,0.));
#1647=VECTOR('',#1646,1.);
#1648=CARTESIAN_POINT('',(0.,48.234216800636,10.795));
#1649=LINE('',#1648,#1647);
#1650=CARTESIAN_POINT('',(0.,48.869216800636,10.795));
#1651=VERTEX_POINT('',#1650);
#1652=EDGE_CURVE('P3_E119',#1627,#1651,#1649,.T.);
#1653=ORIENTED_EDGE('',*,*,#1652,.T.);
#1654=CARTESIAN_POINT('',(0.,48.869216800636,0.));
#1655=DIRECTION('',(0.,-1.,0.));
#1656=DIRECTION('',(1.,0.,0.));
#1657=AXIS2_PLACEMENT_3D('',#1654,#1655,#1656);
#1658=CIRCLE('',#1657,10.795);
#1659=CARTESIAN_POINT('',(0.,48.869216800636,-10.795));
#1660=VERTEX_POINT('',#1659);
#1661=EDGE_CURVE('P3_E106',#1660,#1651,#1658,.T.);
#1662=ORIENTED_EDGE('',*,*,#1661,.F.);
#1663=CARTESIAN_POINT('',(0.,48.869216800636,0.));
#1664=DIRECTION('',(0.,-1.,0.));
#1665=DIRECTION('',(1.,0.,0.));
#1666=AXIS2_PLACEMENT_3D('',#1663,#1664,#1665);
#1667=CIRCLE('',#1666,10.795);
#1668=EDGE_CURVE('P3_E109',#1651,#1660,#1667,.T.);
#1669=ORIENTED_EDGE('',*,*,#1668,.F.);
#1670=ORIENTED_EDGE('',*,*,#1652,.F.);
#1671=ORIENTED_EDGE('',*,*,#1635,.T.);
#1672=EDGE_LOOP('',(#1645,#1653,#1662,#1669,#1670,#1671));
#1673=FACE_BOUND('',#1672,.T.);
#1674=ADVANCED_FACE('P3_F134',(#1673),#1644,.F.);
#1675=CARTESIAN_POINT('',(0.,48.869216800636,-14.859));
#1676=DIRECTION('',(0.,1.,0.));
#1677=DIRECTION('',(1.,0.,0.));
#1678=AXIS2_PLACEMENT_3D('',#1675,#1676,#1677);
#1679=PLANE('',#1678);
#1680=CARTESIAN_POINT('',(0.,48.869216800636,0.));
#1681=DIRECTION('',(0.,-1.,0.));
#1682=DIRECTION('',(1.,0.,0.));
#1683=AXIS2_PLACEMENT_3D('',#1680,#1681,#1682);
#1684=CIRCLE('',#1683,14.859);
#1685=CARTESIAN_POINT('',(0.,48.869216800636,-14.859));
#1686=VERTEX_POINT('',#1685);
#1687=CARTESIAN_POINT('',(0.,48.869216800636,14.859));
#1688=VERTEX_POINT('',#1687);
#1689=EDGE_CURVE('P3_E91',#1686,#1688,#1684,.T.);
#1690=ORIENTED_EDGE('',*,*,#1689,.F.);
#1691=CARTESIAN_POINT('',(0.,48.869216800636,0.));
#1692=DIRECTION('',(0.,-1.,0.));
#1693=DIRECTION('',(1.,0.,0.));
#1694=AXIS2_PLACEMENT_3D('',#1691,#1692,#1693);
#1695=CIRCLE('',#1694,14.859);
#1696=EDGE_CURVE('P3_E84',#1688,#1686,#1695,.T.);
#1697=ORIENTED_EDGE('',*,*,#1696,.F.);
#1698=EDGE_LOOP('',(#1690,#1697));
#1699=FACE_BOUND('',#1698,.T.);
#1700=ORIENTED_EDGE('',*,*,#1661,.T.);
#1701=ORIENTED_EDGE('',*,*,#1668,.T.);
#1702=EDGE_LOOP('',(#1700,#1701));
#1703=FACE_BOUND('',#1702,.T.);
#1704=ADVANCED_FACE('P3_F132',(#1699,#1703),#1679,.T.);
#1705=CARTESIAN_POINT('',(0.,50.456716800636,0.));
#1706=DIRECTION('',(0.,-1.,0.));
#1707=DIRECTION('',(0.,0.,-1.));
#1708=AXIS2_PLACEMENT_3D('',#1705,#1706,#1707);
#1709=CYLINDRICAL_SURFACE('',#1708,14.859);
#1710=ORIENTED_EDGE('',*,*,#1689,.T.);
#1711=DIRECTION('',(0.,1.,0.));
#1712=VECTOR('',#1711,1.);
#1713=CARTESIAN_POINT('',(0.,50.456716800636,14.859));
#1714=LINE('',#1713,#1712);
#1715=CARTESIAN_POINT('',(0.,52.044216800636,14.859));
#1716=VERTEX_POINT('',#1715);
#1717=EDGE_CURVE('P3_E88',#1688,#1716,#1714,.T.);
#1718=ORIENTED_EDGE('',*,*,#1717,.T.);
#1719=CARTESIAN_POINT('',(0.,52.044216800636,0.));
#1720=DIRECTION('',(0.,-1.,0.));
#1721=DIRECTION('',(1.,0.,0.));
#1722=AXIS2_PLACEMENT_3D('',#1719,#1720,#1721);
#1723=CIRCLE('',#1722,14.859);
#1724=CARTESIAN_POINT('',(0.,52.044216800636,-14.859));
#1725=VERTEX_POINT('',#1724);
#1726=EDGE_CURVE('P3_E78',#1725,#1716,#1723,.T.);
#1727=ORIENTED_EDGE('',*,*,#1726,.F.);
#1728=CARTESIAN_POINT('',(0.,52.044216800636,0.));
#1729=DIRECTION('',(0.,-1.,0.));
#1730=DIRECTION('',(1.,0.,0.));
#1731=AXIS2_PLACEMENT_3D('',#1728,#1729,#1730);
#1732=CIRCLE('',#1731,14.859);
#1733=EDGE_CURVE('P3_E81',#1716,#1725,#1732,.T.);
#1734=ORIENTED_EDGE('',*,*,#1733,.F.);
#1735=ORIENTED_EDGE('',*,*,#1717,.F.);
#1736=ORIENTED_EDGE('',*,*,#1696,.T.);
#1737=EDGE_LOOP('',(#1710,#1718,#1727,#1734,#1735,#1736));
#1738=FACE_BOUND('',#1737,.T.);
#1739=ADVANCED_FACE('P3_F89',(#1738),#1709,.F.);
#1740=CARTESIAN_POINT('',(0.,52.044216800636,-16.129));
#1741=DIRECTION('',(0.,1.,0.));
#1742=DIRECTION('',(1.,0.,0.));
#1743=AXIS2_PLACEMENT_3D('',#1740,#1741,#1742);
#1744=PLANE('',#1743);
#1745=CARTESIAN_POINT('',(0.,52.044216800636,0.));
#1746=DIRECTION('',(0.,-1.,0.));
#1747=DIRECTION('',(1.,0.,0.));
#1748=AXIS2_PLACEMENT_3D('',#1745,#1746,#1747);
#1749=CIRCLE('',#1748,16.129);
#1750=CARTESIAN_POINT('',(0.,52.044216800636,-16.129));
#1751=VERTEX_POINT('',#1750);
#1752=CARTESIAN_POINT('',(0.,52.044216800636,16.129));
#1753=VERTEX_POINT('',#1752);
#1754=EDGE_CURVE('P3_E104',#1751,#1753,#1749,.T.);
#1755=ORIENTED_EDGE('',*,*,#1754,.F.);
#1756=CARTESIAN_POINT('',(0.,52.044216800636,0.));
#1757=DIRECTION('',(0.,-1.,0.));
#1758=DIRECTION('',(1.,0.,0.));
#1759=AXIS2_PLACEMENT_3D('',#1756,#1757,#1758);
#1760=CIRCLE('',#1759,16.129);
#1761=EDGE_CURVE('P3_E101',#1753,#1751,#1760,.T.);
#1762=ORIENTED_EDGE('',*,*,#1761,.F.);
#1763=EDGE_LOOP('',(#1755,#1762));
#1764=FACE_BOUND('',#1763,.T.);
#1765=ORIENTED_EDGE('',*,*,#1726,.T.);
#1766=ORIENTED_EDGE('',*,*,#1733,.T.);
#1767=EDGE_LOOP('',(#1765,#1766));
#1768=FACE_BOUND('',#1767,.T.);
#1769=ADVANCED_FACE('P3_F17',(#1764,#1768),#1744,.T.);
#1770=CARTESIAN_POINT('',(0.,49.821716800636,0.));
#1771=DIRECTION('',(0.,-1.,0.));
#1772=DIRECTION('',(0.,0.,-1.));
#1773=AXIS2_PLACEMENT_3D('',#1770,#1771,#1772);
#1774=CYLINDRICAL_SURFACE('',#1773,16.129);
#1775=ORIENTED_EDGE('',*,*,#1608,.F.);
#1776=ORIENTED_EDGE('',*,*,#1615,.F.);
#1777=DIRECTION('',(0.,1.,0.));
#1778=VECTOR('',#1777,1.);
#1779=CARTESIAN_POINT('',(0.,49.821716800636,16.129));
#1780=LINE('',#1779,#1778);
#1781=EDGE_CURVE('P3_E95',#1607,#1753,#1780,.T.);
#1782=ORIENTED_EDGE('',*,*,#1781,.T.);
#1783=ORIENTED_EDGE('',*,*,#1761,.T.);
#1784=ORIENTED_EDGE('',*,*,#1754,.T.);
#1785=ORIENTED_EDGE('',*,*,#1781,.F.);
#1786=EDGE_LOOP('',(#1775,#1776,#1782,#1783,#1784,#1785));
#1787=FACE_BOUND('',#1786,.T.);
#1788=ADVANCED_FACE('P3_F169',(#1787),#1774,.T.);
#1789=CLOSED_SHELL('',(#1639,#1674,#1704,#1739,#1769,#1788));
#1790=MANIFOLD_SOLID_BREP('P3_B1',#1789);
#1791=ADVANCED_BREP_SHAPE_REPRESENTATION('',(#18,#1025,#1461,#1593,#1790),#14);
#1792=SHAPE_DEFINITION_REPRESENTATION(#9,#1791);
ENDSEC;
END-ISO-10303-21;
